VERSION 5.7 ;
  NOWIREEXTENSIONATPIN ON ;
  DIVIDERCHAR "/" ;
  BUSBITCHARS "[]" ;
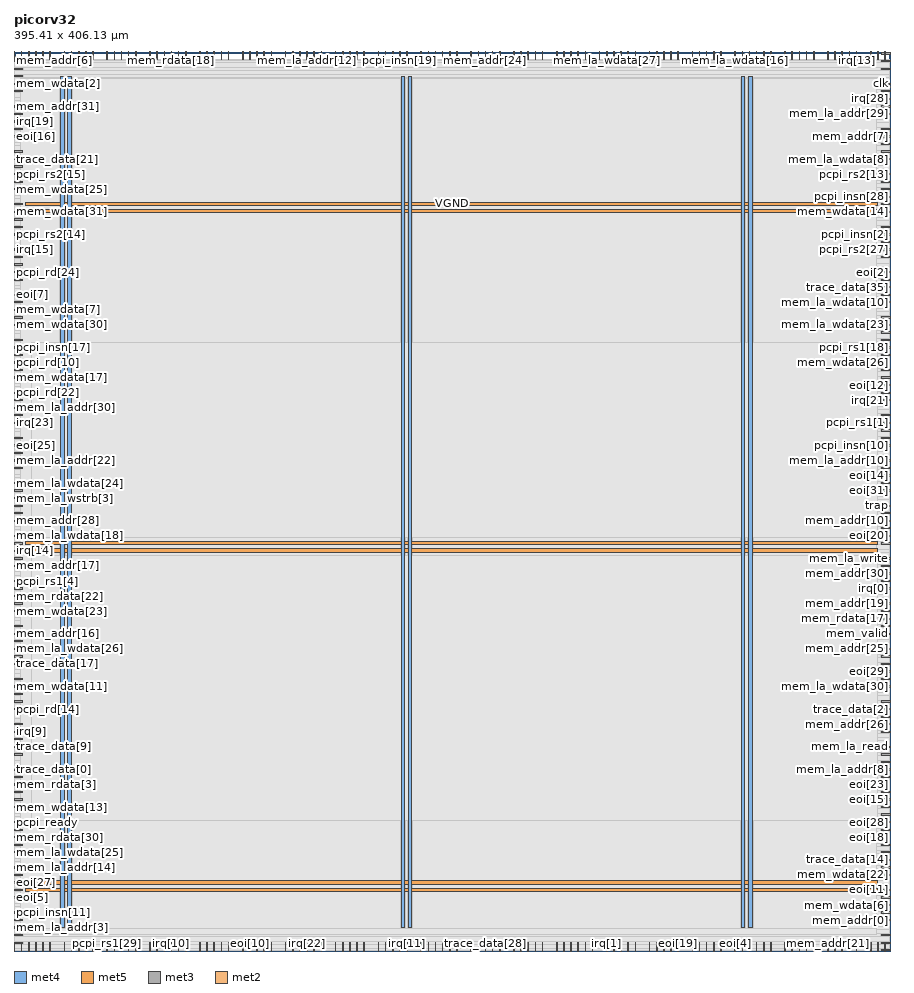
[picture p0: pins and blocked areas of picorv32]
MACRO picorv32
  CLASS BLOCK ;
  FOREIGN picorv32 ;
  ORIGIN 0.000 0.000 ;
  SIZE 395.410 BY 406.130 ;
  PIN VGND
    DIRECTION INOUT ;
    USE GROUND ;
    PORT
      LAYER met4 ;
        RECT 24.340 10.640 25.940 394.640 ;
    END
    PORT
      LAYER met4 ;
        RECT 177.940 10.640 179.540 394.640 ;
    END
    PORT
      LAYER met4 ;
        RECT 331.540 10.640 333.140 394.640 ;
    END
    PORT
      LAYER met5 ;
        RECT 5.280 30.030 389.860 31.630 ;
    END
    PORT
      LAYER met5 ;
        RECT 5.280 183.210 389.860 184.810 ;
    END
    PORT
      LAYER met5 ;
        RECT 5.280 336.390 389.860 337.990 ;
    END
  END VGND
  PIN VPWR
    DIRECTION INOUT ;
    USE POWER ;
    PORT
      LAYER met4 ;
        RECT 21.040 10.640 22.640 394.640 ;
    END
    PORT
      LAYER met4 ;
        RECT 174.640 10.640 176.240 394.640 ;
    END
    PORT
      LAYER met4 ;
        RECT 328.240 10.640 329.840 394.640 ;
    END
    PORT
      LAYER met5 ;
        RECT 5.280 26.730 389.860 28.330 ;
    END
    PORT
      LAYER met5 ;
        RECT 5.280 179.910 389.860 181.510 ;
    END
    PORT
      LAYER met5 ;
        RECT 5.280 333.090 389.860 334.690 ;
    END
  END VPWR
  PIN clk
    DIRECTION INPUT ;
    USE SIGNAL ;
    ANTENNAGATEAREA 1.286700 ;
    ANTENNADIFFAREA 0.434700 ;
    PORT
      LAYER met3 ;
        RECT 391.410 391.040 395.410 391.640 ;
    END
  END clk
  PIN eoi[0]
    DIRECTION OUTPUT TRISTATE ;
    USE SIGNAL ;
    PORT
      LAYER met3 ;
        RECT 0.000 394.440 4.000 395.040 ;
    END
  END eoi[0]
  PIN eoi[10]
    DIRECTION OUTPUT TRISTATE ;
    USE SIGNAL ;
    PORT
      LAYER met2 ;
        RECT 106.350 0.000 106.630 4.000 ;
    END
  END eoi[10]
  PIN eoi[11]
    DIRECTION OUTPUT TRISTATE ;
    USE SIGNAL ;
    PORT
      LAYER met3 ;
        RECT 391.410 27.240 395.410 27.840 ;
    END
  END eoi[11]
  PIN eoi[12]
    DIRECTION OUTPUT TRISTATE ;
    USE SIGNAL ;
    PORT
      LAYER met3 ;
        RECT 391.410 255.040 395.410 255.640 ;
    END
  END eoi[12]
  PIN eoi[13]
    DIRECTION OUTPUT TRISTATE ;
    USE SIGNAL ;
    PORT
      LAYER met2 ;
        RECT 338.190 402.130 338.470 406.130 ;
    END
  END eoi[13]
  PIN eoi[14]
    DIRECTION OUTPUT TRISTATE ;
    USE SIGNAL ;
    PORT
      LAYER met3 ;
        RECT 391.410 214.240 395.410 214.840 ;
    END
  END eoi[14]
  PIN eoi[15]
    DIRECTION OUTPUT TRISTATE ;
    USE SIGNAL ;
    PORT
      LAYER met3 ;
        RECT 391.410 68.040 395.410 68.640 ;
    END
  END eoi[15]
  PIN eoi[16]
    DIRECTION OUTPUT TRISTATE ;
    USE SIGNAL ;
    PORT
      LAYER met3 ;
        RECT 0.000 367.240 4.000 367.840 ;
    END
  END eoi[16]
  PIN eoi[17]
    DIRECTION OUTPUT TRISTATE ;
    USE SIGNAL ;
    PORT
      LAYER met3 ;
        RECT 0.000 326.440 4.000 327.040 ;
    END
  END eoi[17]
  PIN eoi[18]
    DIRECTION OUTPUT TRISTATE ;
    USE SIGNAL ;
    PORT
      LAYER met3 ;
        RECT 391.410 54.440 395.410 55.040 ;
    END
  END eoi[18]
  PIN eoi[19]
    DIRECTION OUTPUT TRISTATE ;
    USE SIGNAL ;
    PORT
      LAYER met2 ;
        RECT 299.550 0.000 299.830 4.000 ;
    END
  END eoi[19]
  PIN eoi[1]
    DIRECTION OUTPUT TRISTATE ;
    USE SIGNAL ;
    PORT
      LAYER met3 ;
        RECT 0.000 17.040 4.000 17.640 ;
    END
  END eoi[1]
  PIN eoi[20]
    DIRECTION OUTPUT TRISTATE ;
    USE SIGNAL ;
    PORT
      LAYER met3 ;
        RECT 391.410 187.040 395.410 187.640 ;
    END
  END eoi[20]
  PIN eoi[21]
    DIRECTION OUTPUT TRISTATE ;
    USE SIGNAL ;
    PORT
      LAYER met3 ;
        RECT 391.410 0.040 395.410 0.640 ;
    END
  END eoi[21]
  PIN eoi[22]
    DIRECTION OUTPUT TRISTATE ;
    USE SIGNAL ;
    PORT
      LAYER met3 ;
        RECT 0.000 370.640 4.000 371.240 ;
    END
  END eoi[22]
  PIN eoi[23]
    DIRECTION OUTPUT TRISTATE ;
    USE SIGNAL ;
    PORT
      LAYER met3 ;
        RECT 391.410 78.240 395.410 78.840 ;
    END
  END eoi[23]
  PIN eoi[24]
    DIRECTION OUTPUT TRISTATE ;
    USE SIGNAL ;
    PORT
      LAYER met2 ;
        RECT 45.170 0.000 45.450 4.000 ;
    END
  END eoi[24]
  PIN eoi[25]
    DIRECTION OUTPUT TRISTATE ;
    USE SIGNAL ;
    PORT
      LAYER met3 ;
        RECT 0.000 227.840 4.000 228.440 ;
    END
  END eoi[25]
  PIN eoi[26]
    DIRECTION OUTPUT TRISTATE ;
    USE SIGNAL ;
    PORT
      LAYER met2 ;
        RECT 164.310 402.130 164.590 406.130 ;
    END
  END eoi[26]
  PIN eoi[27]
    DIRECTION OUTPUT TRISTATE ;
    USE SIGNAL ;
    PORT
      LAYER met3 ;
        RECT 0.000 30.640 4.000 31.240 ;
    END
  END eoi[27]
  PIN eoi[28]
    DIRECTION OUTPUT TRISTATE ;
    USE SIGNAL ;
    PORT
      LAYER met3 ;
        RECT 391.410 57.840 395.410 58.440 ;
    END
  END eoi[28]
  PIN eoi[29]
    DIRECTION OUTPUT TRISTATE ;
    USE SIGNAL ;
    PORT
      LAYER met3 ;
        RECT 391.410 125.840 395.410 126.440 ;
    END
  END eoi[29]
  PIN eoi[2]
    DIRECTION OUTPUT TRISTATE ;
    USE SIGNAL ;
    PORT
      LAYER met3 ;
        RECT 391.410 306.040 395.410 306.640 ;
    END
  END eoi[2]
  PIN eoi[30]
    DIRECTION OUTPUT TRISTATE ;
    USE SIGNAL ;
    PORT
      LAYER met2 ;
        RECT 328.530 0.000 328.810 4.000 ;
    END
  END eoi[30]
  PIN eoi[31]
    DIRECTION OUTPUT TRISTATE ;
    USE SIGNAL ;
    PORT
      LAYER met3 ;
        RECT 391.410 210.840 395.410 211.440 ;
    END
  END eoi[31]
  PIN eoi[3]
    DIRECTION OUTPUT TRISTATE ;
    USE SIGNAL ;
    PORT
      LAYER met2 ;
        RECT 116.010 402.130 116.290 406.130 ;
    END
  END eoi[3]
  PIN eoi[4]
    DIRECTION OUTPUT TRISTATE ;
    USE SIGNAL ;
    PORT
      LAYER met2 ;
        RECT 325.310 0.000 325.590 4.000 ;
    END
  END eoi[4]
  PIN eoi[5]
    DIRECTION OUTPUT TRISTATE ;
    USE SIGNAL ;
    PORT
      LAYER met3 ;
        RECT 0.000 27.240 4.000 27.840 ;
    END
  END eoi[5]
  PIN eoi[6]
    DIRECTION OUTPUT TRISTATE ;
    USE SIGNAL ;
    PORT
      LAYER met2 ;
        RECT 312.430 0.000 312.710 4.000 ;
    END
  END eoi[6]
  PIN eoi[7]
    DIRECTION OUTPUT TRISTATE ;
    USE SIGNAL ;
    PORT
      LAYER met3 ;
        RECT 0.000 292.440 4.000 293.040 ;
    END
  END eoi[7]
  PIN eoi[8]
    DIRECTION OUTPUT TRISTATE ;
    USE SIGNAL ;
    PORT
      LAYER met2 ;
        RECT 289.890 402.130 290.170 406.130 ;
    END
  END eoi[8]
  PIN eoi[9]
    DIRECTION OUTPUT TRISTATE ;
    USE SIGNAL ;
    PORT
      LAYER met2 ;
        RECT 215.830 402.130 216.110 406.130 ;
    END
  END eoi[9]
  PIN irq[0]
    DIRECTION INPUT ;
    USE SIGNAL ;
    PORT
      LAYER met3 ;
        RECT 391.410 163.240 395.410 163.840 ;
    END
  END irq[0]
  PIN irq[10]
    DIRECTION INPUT ;
    USE SIGNAL ;
    PORT
      LAYER met2 ;
        RECT 70.930 0.000 71.210 4.000 ;
    END
  END irq[10]
  PIN irq[11]
    DIRECTION INPUT ;
    USE SIGNAL ;
    PORT
      LAYER met2 ;
        RECT 177.190 0.000 177.470 4.000 ;
    END
  END irq[11]
  PIN irq[12]
    DIRECTION INPUT ;
    USE SIGNAL ;
    PORT
      LAYER met2 ;
        RECT 238.370 402.130 238.650 406.130 ;
    END
  END irq[12]
  PIN irq[13]
    DIRECTION INPUT ;
    USE SIGNAL ;
    PORT
      LAYER met2 ;
        RECT 380.050 402.130 380.330 406.130 ;
    END
  END irq[13]
  PIN irq[14]
    DIRECTION INPUT ;
    USE SIGNAL ;
    PORT
      LAYER met3 ;
        RECT 0.000 180.240 4.000 180.840 ;
    END
  END irq[14]
  PIN irq[15]
    DIRECTION INPUT ;
    USE SIGNAL ;
    PORT
      LAYER met3 ;
        RECT 0.000 316.240 4.000 316.840 ;
    END
  END irq[15]
  PIN irq[16]
    DIRECTION INPUT ;
    USE SIGNAL ;
    PORT
      LAYER met2 ;
        RECT 392.930 402.130 393.210 406.130 ;
    END
  END irq[16]
  PIN irq[17]
    DIRECTION INPUT ;
    USE SIGNAL ;
    PORT
      LAYER met2 ;
        RECT 219.050 402.130 219.330 406.130 ;
    END
  END irq[17]
  PIN irq[18]
    DIRECTION INPUT ;
    USE SIGNAL ;
    PORT
      LAYER met2 ;
        RECT 296.330 402.130 296.610 406.130 ;
    END
  END irq[18]
  PIN irq[19]
    DIRECTION INPUT ;
    USE SIGNAL ;
    PORT
      LAYER met3 ;
        RECT 0.000 374.040 4.000 374.640 ;
    END
  END irq[19]
  PIN irq[1]
    DIRECTION INPUT ;
    USE SIGNAL ;
    PORT
      LAYER met2 ;
        RECT 267.350 0.000 267.630 4.000 ;
    END
  END irq[1]
  PIN irq[20]
    DIRECTION INPUT ;
    USE SIGNAL ;
    PORT
      LAYER met3 ;
        RECT 0.000 401.240 4.000 401.840 ;
    END
  END irq[20]
  PIN irq[21]
    DIRECTION INPUT ;
    USE SIGNAL ;
    PORT
      LAYER met3 ;
        RECT 391.410 248.240 395.410 248.840 ;
    END
  END irq[21]
  PIN irq[22]
    DIRECTION INPUT ;
    USE SIGNAL ;
    PORT
      LAYER met2 ;
        RECT 132.110 0.000 132.390 4.000 ;
    END
  END irq[22]
  PIN irq[23]
    DIRECTION INPUT ;
    USE SIGNAL ;
    PORT
      LAYER met3 ;
        RECT 0.000 238.040 4.000 238.640 ;
    END
  END irq[23]
  PIN irq[24]
    DIRECTION INPUT ;
    USE SIGNAL ;
    PORT
      LAYER met3 ;
        RECT 391.410 404.640 395.410 405.240 ;
    END
  END irq[24]
  PIN irq[25]
    DIRECTION INPUT ;
    USE SIGNAL ;
    PORT
      LAYER met2 ;
        RECT 93.470 402.130 93.750 406.130 ;
    END
  END irq[25]
  PIN irq[26]
    DIRECTION INPUT ;
    USE SIGNAL ;
    PORT
      LAYER met2 ;
        RECT 164.310 0.000 164.590 4.000 ;
    END
  END irq[26]
  PIN irq[27]
    DIRECTION INPUT ;
    USE SIGNAL ;
    PORT
      LAYER met2 ;
        RECT 196.510 402.130 196.790 406.130 ;
    END
  END irq[27]
  PIN irq[28]
    DIRECTION INPUT ;
    USE SIGNAL ;
    PORT
      LAYER met3 ;
        RECT 391.410 384.240 395.410 384.840 ;
    END
  END irq[28]
  PIN irq[29]
    DIRECTION INPUT ;
    USE SIGNAL ;
    PORT
      LAYER met3 ;
        RECT 391.410 47.640 395.410 48.240 ;
    END
  END irq[29]
  PIN irq[2]
    DIRECTION INPUT ;
    USE SIGNAL ;
    PORT
      LAYER met3 ;
        RECT 0.000 122.440 4.000 123.040 ;
    END
  END irq[2]
  PIN irq[30]
    DIRECTION INPUT ;
    USE SIGNAL ;
    PORT
      LAYER met2 ;
        RECT 228.710 0.000 228.990 4.000 ;
    END
  END irq[30]
  PIN irq[31]
    DIRECTION INPUT ;
    USE SIGNAL ;
    PORT
      LAYER met2 ;
        RECT 90.250 402.130 90.530 406.130 ;
    END
  END irq[31]
  PIN irq[3]
    DIRECTION INPUT ;
    USE SIGNAL ;
    PORT
      LAYER met2 ;
        RECT 35.510 0.000 35.790 4.000 ;
    END
  END irq[3]
  PIN irq[4]
    DIRECTION INPUT ;
    USE SIGNAL ;
    PORT
      LAYER met2 ;
        RECT 74.150 402.130 74.430 406.130 ;
    END
  END irq[4]
  PIN irq[5]
    DIRECTION INPUT ;
    USE SIGNAL ;
    PORT
      LAYER met3 ;
        RECT 391.410 360.440 395.410 361.040 ;
    END
  END irq[5]
  PIN irq[6]
    DIRECTION INPUT ;
    USE SIGNAL ;
    PORT
      LAYER met3 ;
        RECT 0.000 88.440 4.000 89.040 ;
    END
  END irq[6]
  PIN irq[7]
    DIRECTION INPUT ;
    USE SIGNAL ;
    PORT
      LAYER met2 ;
        RECT 6.530 402.130 6.810 406.130 ;
    END
  END irq[7]
  PIN irq[8]
    DIRECTION INPUT ;
    USE SIGNAL ;
    PORT
      LAYER met2 ;
        RECT 277.010 0.000 277.290 4.000 ;
    END
  END irq[8]
  PIN irq[9]
    DIRECTION INPUT ;
    USE SIGNAL ;
    PORT
      LAYER met3 ;
        RECT 0.000 98.640 4.000 99.240 ;
    END
  END irq[9]
  PIN mem_addr[0]
    DIRECTION OUTPUT TRISTATE ;
    USE SIGNAL ;
    PORT
      LAYER met3 ;
        RECT 391.410 13.640 395.410 14.240 ;
    END
  END mem_addr[0]
  PIN mem_addr[10]
    DIRECTION OUTPUT TRISTATE ;
    USE SIGNAL ;
    ANTENNADIFFAREA 0.795200 ;
    PORT
      LAYER met3 ;
        RECT 391.410 193.840 395.410 194.440 ;
    END
  END mem_addr[10]
  PIN mem_addr[11]
    DIRECTION OUTPUT TRISTATE ;
    USE SIGNAL ;
    ANTENNADIFFAREA 0.795200 ;
    PORT
      LAYER met3 ;
        RECT 391.410 346.840 395.410 347.440 ;
    END
  END mem_addr[11]
  PIN mem_addr[12]
    DIRECTION OUTPUT TRISTATE ;
    USE SIGNAL ;
    ANTENNADIFFAREA 0.795200 ;
    PORT
      LAYER met3 ;
        RECT 391.410 44.240 395.410 44.840 ;
    END
  END mem_addr[12]
  PIN mem_addr[13]
    DIRECTION OUTPUT TRISTATE ;
    USE SIGNAL ;
    ANTENNADIFFAREA 0.795200 ;
    PORT
      LAYER met2 ;
        RECT 228.710 402.130 228.990 406.130 ;
    END
  END mem_addr[13]
  PIN mem_addr[14]
    DIRECTION OUTPUT TRISTATE ;
    USE SIGNAL ;
    ANTENNADIFFAREA 0.795200 ;
    PORT
      LAYER met2 ;
        RECT 328.530 402.130 328.810 406.130 ;
    END
  END mem_addr[14]
  PIN mem_addr[15]
    DIRECTION OUTPUT TRISTATE ;
    USE SIGNAL ;
    ANTENNADIFFAREA 0.795200 ;
    PORT
      LAYER met2 ;
        RECT 231.930 0.000 232.210 4.000 ;
    END
  END mem_addr[15]
  PIN mem_addr[16]
    DIRECTION OUTPUT TRISTATE ;
    USE SIGNAL ;
    ANTENNADIFFAREA 0.795200 ;
    PORT
      LAYER met3 ;
        RECT 0.000 142.840 4.000 143.440 ;
    END
  END mem_addr[16]
  PIN mem_addr[17]
    DIRECTION OUTPUT TRISTATE ;
    USE SIGNAL ;
    ANTENNADIFFAREA 0.795200 ;
    PORT
      LAYER met3 ;
        RECT 0.000 173.440 4.000 174.040 ;
    END
  END mem_addr[17]
  PIN mem_addr[18]
    DIRECTION OUTPUT TRISTATE ;
    USE SIGNAL ;
    ANTENNADIFFAREA 0.795200 ;
    PORT
      LAYER met2 ;
        RECT 61.270 402.130 61.550 406.130 ;
    END
  END mem_addr[18]
  PIN mem_addr[19]
    DIRECTION OUTPUT TRISTATE ;
    USE SIGNAL ;
    ANTENNADIFFAREA 0.795200 ;
    PORT
      LAYER met3 ;
        RECT 391.410 156.440 395.410 157.040 ;
    END
  END mem_addr[19]
  PIN mem_addr[1]
    DIRECTION OUTPUT TRISTATE ;
    USE SIGNAL ;
    PORT
      LAYER met2 ;
        RECT 90.250 0.000 90.530 4.000 ;
    END
  END mem_addr[1]
  PIN mem_addr[20]
    DIRECTION OUTPUT TRISTATE ;
    USE SIGNAL ;
    ANTENNADIFFAREA 0.795200 ;
    PORT
      LAYER met3 ;
        RECT 0.000 6.840 4.000 7.440 ;
    END
  END mem_addr[20]
  PIN mem_addr[21]
    DIRECTION OUTPUT TRISTATE ;
    USE SIGNAL ;
    ANTENNADIFFAREA 0.795200 ;
    PORT
      LAYER met2 ;
        RECT 367.170 0.000 367.450 4.000 ;
    END
  END mem_addr[21]
  PIN mem_addr[22]
    DIRECTION OUTPUT TRISTATE ;
    USE SIGNAL ;
    ANTENNADIFFAREA 0.795200 ;
    PORT
      LAYER met2 ;
        RECT 238.370 0.000 238.650 4.000 ;
    END
  END mem_addr[22]
  PIN mem_addr[23]
    DIRECTION OUTPUT TRISTATE ;
    USE SIGNAL ;
    ANTENNADIFFAREA 0.795200 ;
    PORT
      LAYER met2 ;
        RECT 360.730 0.000 361.010 4.000 ;
    END
  END mem_addr[23]
  PIN mem_addr[24]
    DIRECTION OUTPUT TRISTATE ;
    USE SIGNAL ;
    ANTENNADIFFAREA 0.795200 ;
    PORT
      LAYER met2 ;
        RECT 212.610 402.130 212.890 406.130 ;
    END
  END mem_addr[24]
  PIN mem_addr[25]
    DIRECTION OUTPUT TRISTATE ;
    USE SIGNAL ;
    ANTENNADIFFAREA 0.795200 ;
    PORT
      LAYER met3 ;
        RECT 391.410 136.040 395.410 136.640 ;
    END
  END mem_addr[25]
  PIN mem_addr[26]
    DIRECTION OUTPUT TRISTATE ;
    USE SIGNAL ;
    ANTENNADIFFAREA 0.795200 ;
    PORT
      LAYER met3 ;
        RECT 391.410 102.040 395.410 102.640 ;
    END
  END mem_addr[26]
  PIN mem_addr[27]
    DIRECTION OUTPUT TRISTATE ;
    USE SIGNAL ;
    ANTENNADIFFAREA 0.795200 ;
    PORT
      LAYER met3 ;
        RECT 0.000 275.440 4.000 276.040 ;
    END
  END mem_addr[27]
  PIN mem_addr[28]
    DIRECTION OUTPUT TRISTATE ;
    USE SIGNAL ;
    ANTENNADIFFAREA 0.795200 ;
    PORT
      LAYER met3 ;
        RECT 0.000 193.840 4.000 194.440 ;
    END
  END mem_addr[28]
  PIN mem_addr[29]
    DIRECTION OUTPUT TRISTATE ;
    USE SIGNAL ;
    ANTENNADIFFAREA 0.795200 ;
    PORT
      LAYER met2 ;
        RECT 96.690 402.130 96.970 406.130 ;
    END
  END mem_addr[29]
  PIN mem_addr[2]
    DIRECTION OUTPUT TRISTATE ;
    USE SIGNAL ;
    ANTENNADIFFAREA 0.795200 ;
    PORT
      LAYER met2 ;
        RECT 154.650 0.000 154.930 4.000 ;
    END
  END mem_addr[2]
  PIN mem_addr[30]
    DIRECTION OUTPUT TRISTATE ;
    USE SIGNAL ;
    ANTENNADIFFAREA 0.795200 ;
    PORT
      LAYER met3 ;
        RECT 391.410 170.040 395.410 170.640 ;
    END
  END mem_addr[30]
  PIN mem_addr[31]
    DIRECTION OUTPUT TRISTATE ;
    USE SIGNAL ;
    ANTENNADIFFAREA 0.795200 ;
    PORT
      LAYER met3 ;
        RECT 0.000 377.440 4.000 378.040 ;
    END
  END mem_addr[31]
  PIN mem_addr[3]
    DIRECTION OUTPUT TRISTATE ;
    USE SIGNAL ;
    ANTENNADIFFAREA 0.795200 ;
    PORT
      LAYER met2 ;
        RECT 251.250 0.000 251.530 4.000 ;
    END
  END mem_addr[3]
  PIN mem_addr[4]
    DIRECTION OUTPUT TRISTATE ;
    USE SIGNAL ;
    ANTENNADIFFAREA 0.795200 ;
    PORT
      LAYER met3 ;
        RECT 0.000 285.640 4.000 286.240 ;
    END
  END mem_addr[4]
  PIN mem_addr[5]
    DIRECTION OUTPUT TRISTATE ;
    USE SIGNAL ;
    ANTENNADIFFAREA 0.795200 ;
    PORT
      LAYER met2 ;
        RECT 231.930 402.130 232.210 406.130 ;
    END
  END mem_addr[5]
  PIN mem_addr[6]
    DIRECTION OUTPUT TRISTATE ;
    USE SIGNAL ;
    ANTENNADIFFAREA 0.795200 ;
    PORT
      LAYER met2 ;
        RECT 16.190 402.130 16.470 406.130 ;
    END
  END mem_addr[6]
  PIN mem_addr[7]
    DIRECTION OUTPUT TRISTATE ;
    USE SIGNAL ;
    ANTENNADIFFAREA 0.445500 ;
    PORT
      LAYER met3 ;
        RECT 391.410 367.240 395.410 367.840 ;
    END
  END mem_addr[7]
  PIN mem_addr[8]
    DIRECTION OUTPUT TRISTATE ;
    USE SIGNAL ;
    ANTENNADIFFAREA 0.795200 ;
    PORT
      LAYER met2 ;
        RECT 25.850 0.000 26.130 4.000 ;
    END
  END mem_addr[8]
  PIN mem_addr[9]
    DIRECTION OUTPUT TRISTATE ;
    USE SIGNAL ;
    ANTENNADIFFAREA 0.795200 ;
    PORT
      LAYER met3 ;
        RECT 0.000 387.640 4.000 388.240 ;
    END
  END mem_addr[9]
  PIN mem_instr
    DIRECTION OUTPUT TRISTATE ;
    USE SIGNAL ;
    ANTENNADIFFAREA 0.795200 ;
    PORT
      LAYER met3 ;
        RECT 0.000 360.440 4.000 361.040 ;
    END
  END mem_instr
  PIN mem_la_addr[0]
    DIRECTION OUTPUT TRISTATE ;
    USE SIGNAL ;
    PORT
      LAYER met3 ;
        RECT 0.000 78.240 4.000 78.840 ;
    END
  END mem_la_addr[0]
  PIN mem_la_addr[10]
    DIRECTION OUTPUT TRISTATE ;
    USE SIGNAL ;
    ANTENNADIFFAREA 0.445500 ;
    PORT
      LAYER met3 ;
        RECT 391.410 221.040 395.410 221.640 ;
    END
  END mem_la_addr[10]
  PIN mem_la_addr[11]
    DIRECTION OUTPUT TRISTATE ;
    USE SIGNAL ;
    ANTENNADIFFAREA 0.795200 ;
    PORT
      LAYER met2 ;
        RECT 0.090 402.130 0.370 406.130 ;
    END
  END mem_la_addr[11]
  PIN mem_la_addr[12]
    DIRECTION OUTPUT TRISTATE ;
    USE SIGNAL ;
    ANTENNADIFFAREA 0.795200 ;
    PORT
      LAYER met2 ;
        RECT 132.110 402.130 132.390 406.130 ;
    END
  END mem_la_addr[12]
  PIN mem_la_addr[13]
    DIRECTION OUTPUT TRISTATE ;
    USE SIGNAL ;
    ANTENNADIFFAREA 0.795200 ;
    PORT
      LAYER met2 ;
        RECT 190.070 0.000 190.350 4.000 ;
    END
  END mem_la_addr[13]
  PIN mem_la_addr[14]
    DIRECTION OUTPUT TRISTATE ;
    USE SIGNAL ;
    ANTENNADIFFAREA 0.795200 ;
    PORT
      LAYER met3 ;
        RECT 0.000 37.440 4.000 38.040 ;
    END
  END mem_la_addr[14]
  PIN mem_la_addr[15]
    DIRECTION OUTPUT TRISTATE ;
    USE SIGNAL ;
    ANTENNADIFFAREA 0.795200 ;
    PORT
      LAYER met2 ;
        RECT 251.250 402.130 251.530 406.130 ;
    END
  END mem_la_addr[15]
  PIN mem_la_addr[16]
    DIRECTION OUTPUT TRISTATE ;
    USE SIGNAL ;
    ANTENNADIFFAREA 0.445500 ;
    PORT
      LAYER met3 ;
        RECT 391.410 278.840 395.410 279.440 ;
    END
  END mem_la_addr[16]
  PIN mem_la_addr[17]
    DIRECTION OUTPUT TRISTATE ;
    USE SIGNAL ;
    ANTENNADIFFAREA 0.795200 ;
    PORT
      LAYER met2 ;
        RECT 3.310 402.130 3.590 406.130 ;
    END
  END mem_la_addr[17]
  PIN mem_la_addr[18]
    DIRECTION OUTPUT TRISTATE ;
    USE SIGNAL ;
    ANTENNADIFFAREA 0.795200 ;
    PORT
      LAYER met2 ;
        RECT 257.690 0.000 257.970 4.000 ;
    END
  END mem_la_addr[18]
  PIN mem_la_addr[19]
    DIRECTION OUTPUT TRISTATE ;
    USE SIGNAL ;
    ANTENNADIFFAREA 0.795200 ;
    PORT
      LAYER met2 ;
        RECT 376.830 0.000 377.110 4.000 ;
    END
  END mem_la_addr[19]
  PIN mem_la_addr[1]
    DIRECTION OUTPUT TRISTATE ;
    USE SIGNAL ;
    PORT
      LAYER met3 ;
        RECT 391.410 71.440 395.410 72.040 ;
    END
  END mem_la_addr[1]
  PIN mem_la_addr[20]
    DIRECTION OUTPUT TRISTATE ;
    USE SIGNAL ;
    ANTENNADIFFAREA 0.795200 ;
    PORT
      LAYER met2 ;
        RECT 9.750 402.130 10.030 406.130 ;
    END
  END mem_la_addr[20]
  PIN mem_la_addr[21]
    DIRECTION OUTPUT TRISTATE ;
    USE SIGNAL ;
    ANTENNADIFFAREA 0.795200 ;
    PORT
      LAYER met2 ;
        RECT 170.750 402.130 171.030 406.130 ;
    END
  END mem_la_addr[21]
  PIN mem_la_addr[22]
    DIRECTION OUTPUT TRISTATE ;
    USE SIGNAL ;
    ANTENNADIFFAREA 0.795200 ;
    PORT
      LAYER met3 ;
        RECT 0.000 224.440 4.000 225.040 ;
    END
  END mem_la_addr[22]
  PIN mem_la_addr[23]
    DIRECTION OUTPUT TRISTATE ;
    USE SIGNAL ;
    ANTENNADIFFAREA 0.795200 ;
    PORT
      LAYER met2 ;
        RECT 77.370 402.130 77.650 406.130 ;
    END
  END mem_la_addr[23]
  PIN mem_la_addr[24]
    DIRECTION OUTPUT TRISTATE ;
    USE SIGNAL ;
    ANTENNADIFFAREA 0.795200 ;
    PORT
      LAYER met2 ;
        RECT 51.610 402.130 51.890 406.130 ;
    END
  END mem_la_addr[24]
  PIN mem_la_addr[25]
    DIRECTION OUTPUT TRISTATE ;
    USE SIGNAL ;
    ANTENNADIFFAREA 0.795200 ;
    PORT
      LAYER met3 ;
        RECT 391.410 343.440 395.410 344.040 ;
    END
  END mem_la_addr[25]
  PIN mem_la_addr[26]
    DIRECTION OUTPUT TRISTATE ;
    USE SIGNAL ;
    ANTENNADIFFAREA 0.795200 ;
    PORT
      LAYER met2 ;
        RECT 48.390 402.130 48.670 406.130 ;
    END
  END mem_la_addr[26]
  PIN mem_la_addr[27]
    DIRECTION OUTPUT TRISTATE ;
    USE SIGNAL ;
    ANTENNADIFFAREA 0.795200 ;
    PORT
      LAYER met3 ;
        RECT 391.410 88.440 395.410 89.040 ;
    END
  END mem_la_addr[27]
  PIN mem_la_addr[28]
    DIRECTION OUTPUT TRISTATE ;
    USE SIGNAL ;
    ANTENNADIFFAREA 0.795200 ;
    PORT
      LAYER met2 ;
        RECT 22.630 402.130 22.910 406.130 ;
    END
  END mem_la_addr[28]
  PIN mem_la_addr[29]
    DIRECTION OUTPUT TRISTATE ;
    USE SIGNAL ;
    ANTENNADIFFAREA 0.795200 ;
    PORT
      LAYER met3 ;
        RECT 391.410 377.440 395.410 378.040 ;
    END
  END mem_la_addr[29]
  PIN mem_la_addr[2]
    DIRECTION OUTPUT TRISTATE ;
    USE SIGNAL ;
    ANTENNADIFFAREA 0.795200 ;
    PORT
      LAYER met3 ;
        RECT 391.410 149.640 395.410 150.240 ;
    END
  END mem_la_addr[2]
  PIN mem_la_addr[30]
    DIRECTION OUTPUT TRISTATE ;
    USE SIGNAL ;
    ANTENNADIFFAREA 0.795200 ;
    PORT
      LAYER met3 ;
        RECT 0.000 241.440 4.000 242.040 ;
    END
  END mem_la_addr[30]
  PIN mem_la_addr[31]
    DIRECTION OUTPUT TRISTATE ;
    USE SIGNAL ;
    ANTENNADIFFAREA 0.795200 ;
    PORT
      LAYER met2 ;
        RECT 138.550 0.000 138.830 4.000 ;
    END
  END mem_la_addr[31]
  PIN mem_la_addr[3]
    DIRECTION OUTPUT TRISTATE ;
    USE SIGNAL ;
    ANTENNADIFFAREA 0.795200 ;
    PORT
      LAYER met3 ;
        RECT 0.000 10.240 4.000 10.840 ;
    END
  END mem_la_addr[3]
  PIN mem_la_addr[4]
    DIRECTION OUTPUT TRISTATE ;
    USE SIGNAL ;
    ANTENNADIFFAREA 0.795200 ;
    PORT
      LAYER met3 ;
        RECT 391.410 326.440 395.410 327.040 ;
    END
  END mem_la_addr[4]
  PIN mem_la_addr[5]
    DIRECTION OUTPUT TRISTATE ;
    USE SIGNAL ;
    ANTENNADIFFAREA 0.795200 ;
    PORT
      LAYER met2 ;
        RECT 331.750 0.000 332.030 4.000 ;
    END
  END mem_la_addr[5]
  PIN mem_la_addr[6]
    DIRECTION OUTPUT TRISTATE ;
    USE SIGNAL ;
    ANTENNADIFFAREA 0.795200 ;
    PORT
      LAYER met3 ;
        RECT 391.410 336.640 395.410 337.240 ;
    END
  END mem_la_addr[6]
  PIN mem_la_addr[7]
    DIRECTION OUTPUT TRISTATE ;
    USE SIGNAL ;
    ANTENNADIFFAREA 0.795200 ;
    PORT
      LAYER met2 ;
        RECT 116.010 0.000 116.290 4.000 ;
    END
  END mem_la_addr[7]
  PIN mem_la_addr[8]
    DIRECTION OUTPUT TRISTATE ;
    USE SIGNAL ;
    ANTENNADIFFAREA 0.795200 ;
    PORT
      LAYER met3 ;
        RECT 391.410 81.640 395.410 82.240 ;
    END
  END mem_la_addr[8]
  PIN mem_la_addr[9]
    DIRECTION OUTPUT TRISTATE ;
    USE SIGNAL ;
    ANTENNADIFFAREA 0.795200 ;
    PORT
      LAYER met2 ;
        RECT 125.670 0.000 125.950 4.000 ;
    END
  END mem_la_addr[9]
  PIN mem_la_read
    DIRECTION OUTPUT TRISTATE ;
    USE SIGNAL ;
    ANTENNADIFFAREA 0.795200 ;
    PORT
      LAYER met3 ;
        RECT 391.410 91.840 395.410 92.440 ;
    END
  END mem_la_read
  PIN mem_la_wdata[0]
    DIRECTION OUTPUT TRISTATE ;
    USE SIGNAL ;
    ANTENNADIFFAREA 0.795200 ;
    PORT
      LAYER met2 ;
        RECT 347.850 402.130 348.130 406.130 ;
    END
  END mem_la_wdata[0]
  PIN mem_la_wdata[10]
    DIRECTION OUTPUT TRISTATE ;
    USE SIGNAL ;
    ANTENNADIFFAREA 0.795200 ;
    PORT
      LAYER met3 ;
        RECT 391.410 292.440 395.410 293.040 ;
    END
  END mem_la_wdata[10]
  PIN mem_la_wdata[11]
    DIRECTION OUTPUT TRISTATE ;
    USE SIGNAL ;
    ANTENNADIFFAREA 0.795200 ;
    PORT
      LAYER met2 ;
        RECT 190.070 402.130 190.350 406.130 ;
    END
  END mem_la_wdata[11]
  PIN mem_la_wdata[12]
    DIRECTION OUTPUT TRISTATE ;
    USE SIGNAL ;
    ANTENNADIFFAREA 0.795200 ;
    PORT
      LAYER met2 ;
        RECT 67.710 402.130 67.990 406.130 ;
    END
  END mem_la_wdata[12]
  PIN mem_la_wdata[13]
    DIRECTION OUTPUT TRISTATE ;
    USE SIGNAL ;
    ANTENNADIFFAREA 0.795200 ;
    PORT
      LAYER met2 ;
        RECT 286.670 0.000 286.950 4.000 ;
    END
  END mem_la_wdata[13]
  PIN mem_la_wdata[14]
    DIRECTION OUTPUT TRISTATE ;
    USE SIGNAL ;
    ANTENNADIFFAREA 0.795200 ;
    PORT
      LAYER met3 ;
        RECT 0.000 329.840 4.000 330.440 ;
    END
  END mem_la_wdata[14]
  PIN mem_la_wdata[15]
    DIRECTION OUTPUT TRISTATE ;
    USE SIGNAL ;
    ANTENNADIFFAREA 0.795200 ;
    PORT
      LAYER met2 ;
        RECT 151.430 402.130 151.710 406.130 ;
    END
  END mem_la_wdata[15]
  PIN mem_la_wdata[16]
    DIRECTION OUTPUT TRISTATE ;
    USE SIGNAL ;
    ANTENNADIFFAREA 0.795200 ;
    PORT
      LAYER met2 ;
        RECT 325.310 402.130 325.590 406.130 ;
    END
  END mem_la_wdata[16]
  PIN mem_la_wdata[17]
    DIRECTION OUTPUT TRISTATE ;
    USE SIGNAL ;
    ANTENNADIFFAREA 0.795200 ;
    PORT
      LAYER met2 ;
        RECT 360.730 402.130 361.010 406.130 ;
    END
  END mem_la_wdata[17]
  PIN mem_la_wdata[18]
    DIRECTION OUTPUT TRISTATE ;
    USE SIGNAL ;
    ANTENNADIFFAREA 0.795200 ;
    PORT
      LAYER met3 ;
        RECT 0.000 187.040 4.000 187.640 ;
    END
  END mem_la_wdata[18]
  PIN mem_la_wdata[19]
    DIRECTION OUTPUT TRISTATE ;
    USE SIGNAL ;
    ANTENNADIFFAREA 0.795200 ;
    PORT
      LAYER met2 ;
        RECT 128.890 0.000 129.170 4.000 ;
    END
  END mem_la_wdata[19]
  PIN mem_la_wdata[1]
    DIRECTION OUTPUT TRISTATE ;
    USE SIGNAL ;
    ANTENNADIFFAREA 0.795200 ;
    PORT
      LAYER met2 ;
        RECT 183.630 0.000 183.910 4.000 ;
    END
  END mem_la_wdata[1]
  PIN mem_la_wdata[20]
    DIRECTION OUTPUT TRISTATE ;
    USE SIGNAL ;
    ANTENNADIFFAREA 0.795200 ;
    PORT
      LAYER met3 ;
        RECT 391.410 285.640 395.410 286.240 ;
    END
  END mem_la_wdata[20]
  PIN mem_la_wdata[21]
    DIRECTION OUTPUT TRISTATE ;
    USE SIGNAL ;
    ANTENNADIFFAREA 0.795200 ;
    PORT
      LAYER met3 ;
        RECT 391.410 234.640 395.410 235.240 ;
    END
  END mem_la_wdata[21]
  PIN mem_la_wdata[22]
    DIRECTION OUTPUT TRISTATE ;
    USE SIGNAL ;
    ANTENNADIFFAREA 0.795200 ;
    PORT
      LAYER met2 ;
        RECT 386.490 0.000 386.770 4.000 ;
    END
  END mem_la_wdata[22]
  PIN mem_la_wdata[23]
    DIRECTION OUTPUT TRISTATE ;
    USE SIGNAL ;
    ANTENNADIFFAREA 0.795200 ;
    PORT
      LAYER met3 ;
        RECT 391.410 282.240 395.410 282.840 ;
    END
  END mem_la_wdata[23]
  PIN mem_la_wdata[24]
    DIRECTION OUTPUT TRISTATE ;
    USE SIGNAL ;
    ANTENNADIFFAREA 0.795200 ;
    PORT
      LAYER met3 ;
        RECT 0.000 210.840 4.000 211.440 ;
    END
  END mem_la_wdata[24]
  PIN mem_la_wdata[25]
    DIRECTION OUTPUT TRISTATE ;
    USE SIGNAL ;
    ANTENNADIFFAREA 0.795200 ;
    PORT
      LAYER met3 ;
        RECT 0.000 44.240 4.000 44.840 ;
    END
  END mem_la_wdata[25]
  PIN mem_la_wdata[26]
    DIRECTION OUTPUT TRISTATE ;
    USE SIGNAL ;
    ANTENNADIFFAREA 0.795200 ;
    PORT
      LAYER met3 ;
        RECT 0.000 139.440 4.000 140.040 ;
    END
  END mem_la_wdata[26]
  PIN mem_la_wdata[27]
    DIRECTION OUTPUT TRISTATE ;
    USE SIGNAL ;
    ANTENNADIFFAREA 0.795200 ;
    PORT
      LAYER met2 ;
        RECT 267.350 402.130 267.630 406.130 ;
    END
  END mem_la_wdata[27]
  PIN mem_la_wdata[28]
    DIRECTION OUTPUT TRISTATE ;
    USE SIGNAL ;
    ANTENNADIFFAREA 0.795200 ;
    PORT
      LAYER met2 ;
        RECT 93.470 0.000 93.750 4.000 ;
    END
  END mem_la_wdata[28]
  PIN mem_la_wdata[29]
    DIRECTION OUTPUT TRISTATE ;
    USE SIGNAL ;
    ANTENNADIFFAREA 0.795200 ;
    PORT
      LAYER met2 ;
        RECT 167.530 402.130 167.810 406.130 ;
    END
  END mem_la_wdata[29]
  PIN mem_la_wdata[2]
    DIRECTION OUTPUT TRISTATE ;
    USE SIGNAL ;
    ANTENNADIFFAREA 0.795200 ;
    PORT
      LAYER met2 ;
        RECT 173.970 0.000 174.250 4.000 ;
    END
  END mem_la_wdata[2]
  PIN mem_la_wdata[30]
    DIRECTION OUTPUT TRISTATE ;
    USE SIGNAL ;
    ANTENNADIFFAREA 0.445500 ;
    PORT
      LAYER met3 ;
        RECT 391.410 119.040 395.410 119.640 ;
    END
  END mem_la_wdata[30]
  PIN mem_la_wdata[31]
    DIRECTION OUTPUT TRISTATE ;
    USE SIGNAL ;
    ANTENNADIFFAREA 0.795200 ;
    PORT
      LAYER met2 ;
        RECT 25.850 402.130 26.130 406.130 ;
    END
  END mem_la_wdata[31]
  PIN mem_la_wdata[3]
    DIRECTION OUTPUT TRISTATE ;
    USE SIGNAL ;
    ANTENNADIFFAREA 0.795200 ;
    PORT
      LAYER met3 ;
        RECT 391.410 98.640 395.410 99.240 ;
    END
  END mem_la_wdata[3]
  PIN mem_la_wdata[4]
    DIRECTION OUTPUT TRISTATE ;
    USE SIGNAL ;
    ANTENNADIFFAREA 0.795200 ;
    PORT
      LAYER met3 ;
        RECT 0.000 112.240 4.000 112.840 ;
    END
  END mem_la_wdata[4]
  PIN mem_la_wdata[5]
    DIRECTION OUTPUT TRISTATE ;
    USE SIGNAL ;
    ANTENNADIFFAREA 0.795200 ;
    PORT
      LAYER met2 ;
        RECT 254.470 0.000 254.750 4.000 ;
    END
  END mem_la_wdata[5]
  PIN mem_la_wdata[6]
    DIRECTION OUTPUT TRISTATE ;
    USE SIGNAL ;
    ANTENNADIFFAREA 0.795200 ;
    PORT
      LAYER met3 ;
        RECT 391.410 397.840 395.410 398.440 ;
    END
  END mem_la_wdata[6]
  PIN mem_la_wdata[7]
    DIRECTION OUTPUT TRISTATE ;
    USE SIGNAL ;
    ANTENNADIFFAREA 0.795200 ;
    PORT
      LAYER met2 ;
        RECT 135.330 0.000 135.610 4.000 ;
    END
  END mem_la_wdata[7]
  PIN mem_la_wdata[8]
    DIRECTION OUTPUT TRISTATE ;
    USE SIGNAL ;
    ANTENNADIFFAREA 0.795200 ;
    PORT
      LAYER met3 ;
        RECT 391.410 357.040 395.410 357.640 ;
    END
  END mem_la_wdata[8]
  PIN mem_la_wdata[9]
    DIRECTION OUTPUT TRISTATE ;
    USE SIGNAL ;
    ANTENNADIFFAREA 0.795200 ;
    PORT
      LAYER met3 ;
        RECT 0.000 176.840 4.000 177.440 ;
    END
  END mem_la_wdata[9]
  PIN mem_la_write
    DIRECTION OUTPUT TRISTATE ;
    USE SIGNAL ;
    ANTENNADIFFAREA 0.795200 ;
    PORT
      LAYER met3 ;
        RECT 391.410 176.840 395.410 177.440 ;
    END
  END mem_la_write
  PIN mem_la_wstrb[0]
    DIRECTION OUTPUT TRISTATE ;
    USE SIGNAL ;
    ANTENNADIFFAREA 0.795200 ;
    PORT
      LAYER met3 ;
        RECT 0.000 309.440 4.000 310.040 ;
    END
  END mem_la_wstrb[0]
  PIN mem_la_wstrb[1]
    DIRECTION OUTPUT TRISTATE ;
    USE SIGNAL ;
    ANTENNADIFFAREA 0.795200 ;
    PORT
      LAYER met3 ;
        RECT 0.000 251.640 4.000 252.240 ;
    END
  END mem_la_wstrb[1]
  PIN mem_la_wstrb[2]
    DIRECTION OUTPUT TRISTATE ;
    USE SIGNAL ;
    ANTENNADIFFAREA 0.795200 ;
    PORT
      LAYER met2 ;
        RECT 280.230 402.130 280.510 406.130 ;
    END
  END mem_la_wstrb[2]
  PIN mem_la_wstrb[3]
    DIRECTION OUTPUT TRISTATE ;
    USE SIGNAL ;
    ANTENNADIFFAREA 0.795200 ;
    PORT
      LAYER met3 ;
        RECT 0.000 204.040 4.000 204.640 ;
    END
  END mem_la_wstrb[3]
  PIN mem_rdata[0]
    DIRECTION INPUT ;
    USE SIGNAL ;
    ANTENNAGATEAREA 0.647700 ;
    ANTENNADIFFAREA 0.434700 ;
    PORT
      LAYER met3 ;
        RECT 0.000 217.640 4.000 218.240 ;
    END
  END mem_rdata[0]
  PIN mem_rdata[10]
    DIRECTION INPUT ;
    USE SIGNAL ;
    ANTENNAGATEAREA 0.593700 ;
    ANTENNADIFFAREA 0.434700 ;
    PORT
      LAYER met2 ;
        RECT 209.390 0.000 209.670 4.000 ;
    END
  END mem_rdata[10]
  PIN mem_rdata[11]
    DIRECTION INPUT ;
    USE SIGNAL ;
    ANTENNAGATEAREA 0.647700 ;
    ANTENNADIFFAREA 0.434700 ;
    PORT
      LAYER met2 ;
        RECT 351.070 0.000 351.350 4.000 ;
    END
  END mem_rdata[11]
  PIN mem_rdata[12]
    DIRECTION INPUT ;
    USE SIGNAL ;
    ANTENNAGATEAREA 0.647700 ;
    ANTENNADIFFAREA 0.434700 ;
    PORT
      LAYER met3 ;
        RECT 0.000 95.240 4.000 95.840 ;
    END
  END mem_rdata[12]
  PIN mem_rdata[13]
    DIRECTION INPUT ;
    USE SIGNAL ;
    ANTENNAGATEAREA 0.593700 ;
    ANTENNADIFFAREA 0.434700 ;
    PORT
      LAYER met2 ;
        RECT 87.030 402.130 87.310 406.130 ;
    END
  END mem_rdata[13]
  PIN mem_rdata[14]
    DIRECTION INPUT ;
    USE SIGNAL ;
    ANTENNAGATEAREA 0.647700 ;
    ANTENNADIFFAREA 0.434700 ;
    PORT
      LAYER met2 ;
        RECT 273.790 0.000 274.070 4.000 ;
    END
  END mem_rdata[14]
  PIN mem_rdata[15]
    DIRECTION INPUT ;
    USE SIGNAL ;
    ANTENNAGATEAREA 0.647700 ;
    ANTENNADIFFAREA 0.434700 ;
    PORT
      LAYER met3 ;
        RECT 0.000 302.640 4.000 303.240 ;
    END
  END mem_rdata[15]
  PIN mem_rdata[16]
    DIRECTION INPUT ;
    USE SIGNAL ;
    ANTENNAGATEAREA 0.647700 ;
    ANTENNADIFFAREA 0.434700 ;
    PORT
      LAYER met2 ;
        RECT 144.990 0.000 145.270 4.000 ;
    END
  END mem_rdata[16]
  PIN mem_rdata[17]
    DIRECTION INPUT ;
    USE SIGNAL ;
    ANTENNAGATEAREA 0.647700 ;
    ANTENNADIFFAREA 0.434700 ;
    PORT
      LAYER met3 ;
        RECT 391.410 153.040 395.410 153.640 ;
    END
  END mem_rdata[17]
  PIN mem_rdata[18]
    DIRECTION INPUT ;
    USE SIGNAL ;
    ANTENNAGATEAREA 0.593700 ;
    ANTENNADIFFAREA 0.434700 ;
    PORT
      LAYER met2 ;
        RECT 70.930 402.130 71.210 406.130 ;
    END
  END mem_rdata[18]
  PIN mem_rdata[19]
    DIRECTION INPUT ;
    USE SIGNAL ;
    ANTENNAGATEAREA 0.647700 ;
    ANTENNADIFFAREA 0.434700 ;
    PORT
      LAYER met2 ;
        RECT 199.730 402.130 200.010 406.130 ;
    END
  END mem_rdata[19]
  PIN mem_rdata[1]
    DIRECTION INPUT ;
    USE SIGNAL ;
    ANTENNAGATEAREA 0.647700 ;
    ANTENNADIFFAREA 0.434700 ;
    PORT
      LAYER met2 ;
        RECT 206.170 402.130 206.450 406.130 ;
    END
  END mem_rdata[1]
  PIN mem_rdata[20]
    DIRECTION INPUT ;
    USE SIGNAL ;
    ANTENNAGATEAREA 0.682200 ;
    ANTENNADIFFAREA 0.434700 ;
    PORT
      LAYER met3 ;
        RECT 391.410 319.640 395.410 320.240 ;
    END
  END mem_rdata[20]
  PIN mem_rdata[21]
    DIRECTION INPUT ;
    USE SIGNAL ;
    ANTENNAGATEAREA 0.647700 ;
    ANTENNADIFFAREA 0.434700 ;
    PORT
      LAYER met2 ;
        RECT 157.870 402.130 158.150 406.130 ;
    END
  END mem_rdata[21]
  PIN mem_rdata[22]
    DIRECTION INPUT ;
    USE SIGNAL ;
    ANTENNAGATEAREA 0.593700 ;
    ANTENNADIFFAREA 0.434700 ;
    PORT
      LAYER met3 ;
        RECT 0.000 159.840 4.000 160.440 ;
    END
  END mem_rdata[22]
  PIN mem_rdata[23]
    DIRECTION INPUT ;
    USE SIGNAL ;
    ANTENNAGATEAREA 0.647700 ;
    ANTENNADIFFAREA 0.434700 ;
    PORT
      LAYER met2 ;
        RECT 193.290 402.130 193.570 406.130 ;
    END
  END mem_rdata[23]
  PIN mem_rdata[24]
    DIRECTION INPUT ;
    USE SIGNAL ;
    ANTENNAGATEAREA 0.682200 ;
    ANTENNADIFFAREA 0.434700 ;
    PORT
      LAYER met2 ;
        RECT 318.870 402.130 319.150 406.130 ;
    END
  END mem_rdata[24]
  PIN mem_rdata[25]
    DIRECTION INPUT ;
    USE SIGNAL ;
    ANTENNAGATEAREA 0.647700 ;
    ANTENNADIFFAREA 0.434700 ;
    PORT
      LAYER met3 ;
        RECT 0.000 23.840 4.000 24.440 ;
    END
  END mem_rdata[25]
  PIN mem_rdata[26]
    DIRECTION INPUT ;
    USE SIGNAL ;
    ANTENNAGATEAREA 0.647700 ;
    ANTENNADIFFAREA 0.434700 ;
    PORT
      LAYER met2 ;
        RECT 112.790 0.000 113.070 4.000 ;
    END
  END mem_rdata[26]
  PIN mem_rdata[27]
    DIRECTION INPUT ;
    USE SIGNAL ;
    ANTENNAGATEAREA 0.682200 ;
    ANTENNADIFFAREA 0.434700 ;
    PORT
      LAYER met2 ;
        RECT 293.110 402.130 293.390 406.130 ;
    END
  END mem_rdata[27]
  PIN mem_rdata[28]
    DIRECTION INPUT ;
    USE SIGNAL ;
    ANTENNAGATEAREA 0.682200 ;
    ANTENNADIFFAREA 0.434700 ;
    PORT
      LAYER met2 ;
        RECT 206.170 0.000 206.450 4.000 ;
    END
  END mem_rdata[28]
  PIN mem_rdata[29]
    DIRECTION INPUT ;
    USE SIGNAL ;
    ANTENNAGATEAREA 0.682200 ;
    ANTENNADIFFAREA 0.434700 ;
    PORT
      LAYER met2 ;
        RECT 351.070 402.130 351.350 406.130 ;
    END
  END mem_rdata[29]
  PIN mem_rdata[2]
    DIRECTION INPUT ;
    USE SIGNAL ;
    ANTENNAGATEAREA 0.647700 ;
    ANTENNADIFFAREA 0.434700 ;
    PORT
      LAYER met2 ;
        RECT 51.610 0.000 51.890 4.000 ;
    END
  END mem_rdata[2]
  PIN mem_rdata[30]
    DIRECTION INPUT ;
    USE SIGNAL ;
    ANTENNAGATEAREA 0.647700 ;
    ANTENNADIFFAREA 0.434700 ;
    PORT
      LAYER met3 ;
        RECT 0.000 54.440 4.000 55.040 ;
    END
  END mem_rdata[30]
  PIN mem_rdata[31]
    DIRECTION INPUT ;
    USE SIGNAL ;
    ANTENNAGATEAREA 0.647700 ;
    ANTENNADIFFAREA 0.434700 ;
    PORT
      LAYER met2 ;
        RECT 167.530 0.000 167.810 4.000 ;
    END
  END mem_rdata[31]
  PIN mem_rdata[3]
    DIRECTION INPUT ;
    USE SIGNAL ;
    ANTENNAGATEAREA 0.647700 ;
    ANTENNADIFFAREA 0.434700 ;
    PORT
      LAYER met3 ;
        RECT 0.000 74.840 4.000 75.440 ;
    END
  END mem_rdata[3]
  PIN mem_rdata[4]
    DIRECTION INPUT ;
    USE SIGNAL ;
    ANTENNAGATEAREA 0.647700 ;
    ANTENNADIFFAREA 0.434700 ;
    PORT
      LAYER met3 ;
        RECT 0.000 166.640 4.000 167.240 ;
    END
  END mem_rdata[4]
  PIN mem_rdata[5]
    DIRECTION INPUT ;
    USE SIGNAL ;
    ANTENNAGATEAREA 0.647700 ;
    ANTENNADIFFAREA 0.434700 ;
    PORT
      LAYER met2 ;
        RECT 144.990 402.130 145.270 406.130 ;
    END
  END mem_rdata[5]
  PIN mem_rdata[6]
    DIRECTION INPUT ;
    USE SIGNAL ;
    ANTENNAGATEAREA 0.593700 ;
    ANTENNADIFFAREA 0.434700 ;
    PORT
      LAYER met3 ;
        RECT 0.000 312.840 4.000 313.440 ;
    END
  END mem_rdata[6]
  PIN mem_rdata[7]
    DIRECTION INPUT ;
    USE SIGNAL ;
    ANTENNAGATEAREA 0.647700 ;
    ANTENNADIFFAREA 0.434700 ;
    PORT
      LAYER met3 ;
        RECT 391.410 61.240 395.410 61.840 ;
    END
  END mem_rdata[7]
  PIN mem_rdata[8]
    DIRECTION INPUT ;
    USE SIGNAL ;
    ANTENNAGATEAREA 0.593700 ;
    ANTENNADIFFAREA 0.434700 ;
    PORT
      LAYER met2 ;
        RECT 186.850 0.000 187.130 4.000 ;
    END
  END mem_rdata[8]
  PIN mem_rdata[9]
    DIRECTION INPUT ;
    USE SIGNAL ;
    ANTENNAGATEAREA 0.647700 ;
    ANTENNADIFFAREA 0.434700 ;
    PORT
      LAYER met2 ;
        RECT 225.490 402.130 225.770 406.130 ;
    END
  END mem_rdata[9]
  PIN mem_ready
    DIRECTION INPUT ;
    USE SIGNAL ;
    ANTENNAGATEAREA 0.631200 ;
    ANTENNADIFFAREA 0.434700 ;
    PORT
      LAYER met3 ;
        RECT 0.000 183.640 4.000 184.240 ;
    END
  END mem_ready
  PIN mem_valid
    DIRECTION OUTPUT TRISTATE ;
    USE SIGNAL ;
    ANTENNADIFFAREA 0.445500 ;
    PORT
      LAYER met3 ;
        RECT 391.410 146.240 395.410 146.840 ;
    END
  END mem_valid
  PIN mem_wdata[0]
    DIRECTION OUTPUT TRISTATE ;
    USE SIGNAL ;
    ANTENNADIFFAREA 0.795200 ;
    PORT
      LAYER met2 ;
        RECT 392.930 0.000 393.210 4.000 ;
    END
  END mem_wdata[0]
  PIN mem_wdata[10]
    DIRECTION OUTPUT TRISTATE ;
    USE SIGNAL ;
    ANTENNADIFFAREA 0.795200 ;
    PORT
      LAYER met2 ;
        RECT 148.210 402.130 148.490 406.130 ;
    END
  END mem_wdata[10]
  PIN mem_wdata[11]
    DIRECTION OUTPUT TRISTATE ;
    USE SIGNAL ;
    ANTENNADIFFAREA 0.795200 ;
    PORT
      LAYER met3 ;
        RECT 0.000 119.040 4.000 119.640 ;
    END
  END mem_wdata[11]
  PIN mem_wdata[12]
    DIRECTION OUTPUT TRISTATE ;
    USE SIGNAL ;
    ANTENNADIFFAREA 0.795200 ;
    PORT
      LAYER met2 ;
        RECT 41.950 402.130 42.230 406.130 ;
    END
  END mem_wdata[12]
  PIN mem_wdata[13]
    DIRECTION OUTPUT TRISTATE ;
    USE SIGNAL ;
    ANTENNADIFFAREA 0.795200 ;
    PORT
      LAYER met3 ;
        RECT 0.000 64.640 4.000 65.240 ;
    END
  END mem_wdata[13]
  PIN mem_wdata[14]
    DIRECTION OUTPUT TRISTATE ;
    USE SIGNAL ;
    ANTENNADIFFAREA 0.445500 ;
    PORT
      LAYER met3 ;
        RECT 391.410 333.240 395.410 333.840 ;
    END
  END mem_wdata[14]
  PIN mem_wdata[15]
    DIRECTION OUTPUT TRISTATE ;
    USE SIGNAL ;
    ANTENNADIFFAREA 0.795200 ;
    PORT
      LAYER met2 ;
        RECT 22.630 0.000 22.910 4.000 ;
    END
  END mem_wdata[15]
  PIN mem_wdata[16]
    DIRECTION OUTPUT TRISTATE ;
    USE SIGNAL ;
    ANTENNADIFFAREA 0.795200 ;
    PORT
      LAYER met2 ;
        RECT 157.870 0.000 158.150 4.000 ;
    END
  END mem_wdata[16]
  PIN mem_wdata[17]
    DIRECTION OUTPUT TRISTATE ;
    USE SIGNAL ;
    ANTENNADIFFAREA 0.795200 ;
    PORT
      LAYER met3 ;
        RECT 0.000 261.840 4.000 262.440 ;
    END
  END mem_wdata[17]
  PIN mem_wdata[18]
    DIRECTION OUTPUT TRISTATE ;
    USE SIGNAL ;
    ANTENNADIFFAREA 0.795200 ;
    PORT
      LAYER met2 ;
        RECT 354.290 0.000 354.570 4.000 ;
    END
  END mem_wdata[18]
  PIN mem_wdata[19]
    DIRECTION OUTPUT TRISTATE ;
    USE SIGNAL ;
    ANTENNADIFFAREA 0.795200 ;
    PORT
      LAYER met3 ;
        RECT 0.000 295.840 4.000 296.440 ;
    END
  END mem_wdata[19]
  PIN mem_wdata[1]
    DIRECTION OUTPUT TRISTATE ;
    USE SIGNAL ;
    ANTENNADIFFAREA 0.795200 ;
    PORT
      LAYER met2 ;
        RECT 248.030 402.130 248.310 406.130 ;
    END
  END mem_wdata[1]
  PIN mem_wdata[20]
    DIRECTION OUTPUT TRISTATE ;
    USE SIGNAL ;
    ANTENNADIFFAREA 0.795200 ;
    PORT
      LAYER met2 ;
        RECT 347.850 0.000 348.130 4.000 ;
    END
  END mem_wdata[20]
  PIN mem_wdata[21]
    DIRECTION OUTPUT TRISTATE ;
    USE SIGNAL ;
    ANTENNADIFFAREA 0.795200 ;
    PORT
      LAYER met2 ;
        RECT 235.150 402.130 235.430 406.130 ;
    END
  END mem_wdata[21]
  PIN mem_wdata[22]
    DIRECTION OUTPUT TRISTATE ;
    USE SIGNAL ;
    ANTENNADIFFAREA 0.445500 ;
    PORT
      LAYER met3 ;
        RECT 391.410 37.440 395.410 38.040 ;
    END
  END mem_wdata[22]
  PIN mem_wdata[23]
    DIRECTION OUTPUT TRISTATE ;
    USE SIGNAL ;
    ANTENNADIFFAREA 0.795200 ;
    PORT
      LAYER met3 ;
        RECT 0.000 153.040 4.000 153.640 ;
    END
  END mem_wdata[23]
  PIN mem_wdata[24]
    DIRECTION OUTPUT TRISTATE ;
    USE SIGNAL ;
    ANTENNADIFFAREA 0.795200 ;
    PORT
      LAYER met3 ;
        RECT 0.000 156.440 4.000 157.040 ;
    END
  END mem_wdata[24]
  PIN mem_wdata[25]
    DIRECTION OUTPUT TRISTATE ;
    USE SIGNAL ;
    ANTENNADIFFAREA 0.795200 ;
    PORT
      LAYER met3 ;
        RECT 0.000 346.840 4.000 347.440 ;
    END
  END mem_wdata[25]
  PIN mem_wdata[26]
    DIRECTION OUTPUT TRISTATE ;
    USE SIGNAL ;
    ANTENNADIFFAREA 0.445500 ;
    PORT
      LAYER met3 ;
        RECT 391.410 268.640 395.410 269.240 ;
    END
  END mem_wdata[26]
  PIN mem_wdata[27]
    DIRECTION OUTPUT TRISTATE ;
    USE SIGNAL ;
    ANTENNADIFFAREA 0.795200 ;
    PORT
      LAYER met2 ;
        RECT 177.190 402.130 177.470 406.130 ;
    END
  END mem_wdata[27]
  PIN mem_wdata[28]
    DIRECTION OUTPUT TRISTATE ;
    USE SIGNAL ;
    ANTENNADIFFAREA 0.795200 ;
    PORT
      LAYER met3 ;
        RECT 0.000 353.640 4.000 354.240 ;
    END
  END mem_wdata[28]
  PIN mem_wdata[29]
    DIRECTION OUTPUT TRISTATE ;
    USE SIGNAL ;
    ANTENNADIFFAREA 0.795200 ;
    PORT
      LAYER met2 ;
        RECT 312.430 402.130 312.710 406.130 ;
    END
  END mem_wdata[29]
  PIN mem_wdata[2]
    DIRECTION OUTPUT TRISTATE ;
    USE SIGNAL ;
    ANTENNADIFFAREA 0.795200 ;
    PORT
      LAYER met3 ;
        RECT 0.000 391.040 4.000 391.640 ;
    END
  END mem_wdata[2]
  PIN mem_wdata[30]
    DIRECTION OUTPUT TRISTATE ;
    USE SIGNAL ;
    ANTENNADIFFAREA 0.795200 ;
    PORT
      LAYER met3 ;
        RECT 0.000 282.240 4.000 282.840 ;
    END
  END mem_wdata[30]
  PIN mem_wdata[31]
    DIRECTION OUTPUT TRISTATE ;
    USE SIGNAL ;
    ANTENNADIFFAREA 0.795200 ;
    PORT
      LAYER met3 ;
        RECT 0.000 333.240 4.000 333.840 ;
    END
  END mem_wdata[31]
  PIN mem_wdata[3]
    DIRECTION OUTPUT TRISTATE ;
    USE SIGNAL ;
    ANTENNADIFFAREA 0.795200 ;
    PORT
      LAYER met3 ;
        RECT 0.000 207.440 4.000 208.040 ;
    END
  END mem_wdata[3]
  PIN mem_wdata[4]
    DIRECTION OUTPUT TRISTATE ;
    USE SIGNAL ;
    ANTENNADIFFAREA 0.795200 ;
    PORT
      LAYER met2 ;
        RECT 103.130 0.000 103.410 4.000 ;
    END
  END mem_wdata[4]
  PIN mem_wdata[5]
    DIRECTION OUTPUT TRISTATE ;
    USE SIGNAL ;
    ANTENNADIFFAREA 0.795200 ;
    PORT
      LAYER met2 ;
        RECT 334.970 0.000 335.250 4.000 ;
    END
  END mem_wdata[5]
  PIN mem_wdata[6]
    DIRECTION OUTPUT TRISTATE ;
    USE SIGNAL ;
    ANTENNADIFFAREA 0.445500 ;
    PORT
      LAYER met3 ;
        RECT 391.410 20.440 395.410 21.040 ;
    END
  END mem_wdata[6]
  PIN mem_wdata[7]
    DIRECTION OUTPUT TRISTATE ;
    USE SIGNAL ;
    ANTENNADIFFAREA 0.795200 ;
    PORT
      LAYER met3 ;
        RECT 0.000 289.040 4.000 289.640 ;
    END
  END mem_wdata[7]
  PIN mem_wdata[8]
    DIRECTION OUTPUT TRISTATE ;
    USE SIGNAL ;
    ANTENNADIFFAREA 0.795200 ;
    PORT
      LAYER met2 ;
        RECT 389.710 402.130 389.990 406.130 ;
    END
  END mem_wdata[8]
  PIN mem_wdata[9]
    DIRECTION OUTPUT TRISTATE ;
    USE SIGNAL ;
    ANTENNADIFFAREA 0.795200 ;
    PORT
      LAYER met2 ;
        RECT 244.810 0.000 245.090 4.000 ;
    END
  END mem_wdata[9]
  PIN mem_wstrb[0]
    DIRECTION OUTPUT TRISTATE ;
    USE SIGNAL ;
    ANTENNADIFFAREA 0.795200 ;
    PORT
      LAYER met3 ;
        RECT 391.410 183.640 395.410 184.240 ;
    END
  END mem_wstrb[0]
  PIN mem_wstrb[1]
    DIRECTION OUTPUT TRISTATE ;
    USE SIGNAL ;
    ANTENNADIFFAREA 0.795200 ;
    PORT
      LAYER met3 ;
        RECT 391.410 142.840 395.410 143.440 ;
    END
  END mem_wstrb[1]
  PIN mem_wstrb[2]
    DIRECTION OUTPUT TRISTATE ;
    USE SIGNAL ;
    ANTENNADIFFAREA 0.795200 ;
    PORT
      LAYER met3 ;
        RECT 391.410 275.440 395.410 276.040 ;
    END
  END mem_wstrb[2]
  PIN mem_wstrb[3]
    DIRECTION OUTPUT TRISTATE ;
    USE SIGNAL ;
    ANTENNADIFFAREA 0.795200 ;
    PORT
      LAYER met3 ;
        RECT 391.410 217.640 395.410 218.240 ;
    END
  END mem_wstrb[3]
  PIN pcpi_insn[0]
    DIRECTION OUTPUT TRISTATE ;
    USE SIGNAL ;
    PORT
      LAYER met2 ;
        RECT 12.970 402.130 13.250 406.130 ;
    END
  END pcpi_insn[0]
  PIN pcpi_insn[10]
    DIRECTION OUTPUT TRISTATE ;
    USE SIGNAL ;
    PORT
      LAYER met3 ;
        RECT 391.410 227.840 395.410 228.440 ;
    END
  END pcpi_insn[10]
  PIN pcpi_insn[11]
    DIRECTION OUTPUT TRISTATE ;
    USE SIGNAL ;
    PORT
      LAYER met3 ;
        RECT 0.000 13.640 4.000 14.240 ;
    END
  END pcpi_insn[11]
  PIN pcpi_insn[12]
    DIRECTION OUTPUT TRISTATE ;
    USE SIGNAL ;
    PORT
      LAYER met2 ;
        RECT 338.190 0.000 338.470 4.000 ;
    END
  END pcpi_insn[12]
  PIN pcpi_insn[13]
    DIRECTION OUTPUT TRISTATE ;
    USE SIGNAL ;
    PORT
      LAYER met2 ;
        RECT 54.830 0.000 55.110 4.000 ;
    END
  END pcpi_insn[13]
  PIN pcpi_insn[14]
    DIRECTION OUTPUT TRISTATE ;
    USE SIGNAL ;
    PORT
      LAYER met3 ;
        RECT 0.000 51.040 4.000 51.640 ;
    END
  END pcpi_insn[14]
  PIN pcpi_insn[15]
    DIRECTION OUTPUT TRISTATE ;
    USE SIGNAL ;
    PORT
      LAYER met2 ;
        RECT 35.510 402.130 35.790 406.130 ;
    END
  END pcpi_insn[15]
  PIN pcpi_insn[16]
    DIRECTION OUTPUT TRISTATE ;
    USE SIGNAL ;
    PORT
      LAYER met3 ;
        RECT 391.410 23.840 395.410 24.440 ;
    END
  END pcpi_insn[16]
  PIN pcpi_insn[17]
    DIRECTION OUTPUT TRISTATE ;
    USE SIGNAL ;
    PORT
      LAYER met3 ;
        RECT 0.000 272.040 4.000 272.640 ;
    END
  END pcpi_insn[17]
  PIN pcpi_insn[18]
    DIRECTION OUTPUT TRISTATE ;
    USE SIGNAL ;
    PORT
      LAYER met2 ;
        RECT 373.610 402.130 373.890 406.130 ;
    END
  END pcpi_insn[18]
  PIN pcpi_insn[19]
    DIRECTION OUTPUT TRISTATE ;
    USE SIGNAL ;
    PORT
      LAYER met2 ;
        RECT 173.970 402.130 174.250 406.130 ;
    END
  END pcpi_insn[19]
  PIN pcpi_insn[1]
    DIRECTION OUTPUT TRISTATE ;
    USE SIGNAL ;
    PORT
      LAYER met2 ;
        RECT 305.990 402.130 306.270 406.130 ;
    END
  END pcpi_insn[1]
  PIN pcpi_insn[20]
    DIRECTION OUTPUT TRISTATE ;
    USE SIGNAL ;
    PORT
      LAYER met2 ;
        RECT 109.570 0.000 109.850 4.000 ;
    END
  END pcpi_insn[20]
  PIN pcpi_insn[21]
    DIRECTION OUTPUT TRISTATE ;
    USE SIGNAL ;
    PORT
      LAYER met3 ;
        RECT 0.000 231.240 4.000 231.840 ;
    END
  END pcpi_insn[21]
  PIN pcpi_insn[22]
    DIRECTION OUTPUT TRISTATE ;
    USE SIGNAL ;
    PORT
      LAYER met2 ;
        RECT 341.410 0.000 341.690 4.000 ;
    END
  END pcpi_insn[22]
  PIN pcpi_insn[23]
    DIRECTION OUTPUT TRISTATE ;
    USE SIGNAL ;
    PORT
      LAYER met2 ;
        RECT 277.010 402.130 277.290 406.130 ;
    END
  END pcpi_insn[23]
  PIN pcpi_insn[24]
    DIRECTION OUTPUT TRISTATE ;
    USE SIGNAL ;
    PORT
      LAYER met2 ;
        RECT 67.710 0.000 67.990 4.000 ;
    END
  END pcpi_insn[24]
  PIN pcpi_insn[25]
    DIRECTION OUTPUT TRISTATE ;
    USE SIGNAL ;
    PORT
      LAYER met3 ;
        RECT 0.000 258.440 4.000 259.040 ;
    END
  END pcpi_insn[25]
  PIN pcpi_insn[26]
    DIRECTION OUTPUT TRISTATE ;
    USE SIGNAL ;
    PORT
      LAYER met3 ;
        RECT 391.410 380.840 395.410 381.440 ;
    END
  END pcpi_insn[26]
  PIN pcpi_insn[27]
    DIRECTION OUTPUT TRISTATE ;
    USE SIGNAL ;
    PORT
      LAYER met3 ;
        RECT 391.410 401.240 395.410 401.840 ;
    END
  END pcpi_insn[27]
  PIN pcpi_insn[28]
    DIRECTION OUTPUT TRISTATE ;
    USE SIGNAL ;
    PORT
      LAYER met3 ;
        RECT 391.410 340.040 395.410 340.640 ;
    END
  END pcpi_insn[28]
  PIN pcpi_insn[29]
    DIRECTION OUTPUT TRISTATE ;
    USE SIGNAL ;
    PORT
      LAYER met2 ;
        RECT 183.630 402.130 183.910 406.130 ;
    END
  END pcpi_insn[29]
  PIN pcpi_insn[2]
    DIRECTION OUTPUT TRISTATE ;
    USE SIGNAL ;
    PORT
      LAYER met3 ;
        RECT 391.410 323.040 395.410 323.640 ;
    END
  END pcpi_insn[2]
  PIN pcpi_insn[30]
    DIRECTION OUTPUT TRISTATE ;
    USE SIGNAL ;
    PORT
      LAYER met2 ;
        RECT 196.510 0.000 196.790 4.000 ;
    END
  END pcpi_insn[30]
  PIN pcpi_insn[31]
    DIRECTION OUTPUT TRISTATE ;
    USE SIGNAL ;
    PORT
      LAYER met2 ;
        RECT 357.510 402.130 357.790 406.130 ;
    END
  END pcpi_insn[31]
  PIN pcpi_insn[3]
    DIRECTION OUTPUT TRISTATE ;
    USE SIGNAL ;
    PORT
      LAYER met2 ;
        RECT 9.750 0.000 10.030 4.000 ;
    END
  END pcpi_insn[3]
  PIN pcpi_insn[4]
    DIRECTION OUTPUT TRISTATE ;
    USE SIGNAL ;
    PORT
      LAYER met2 ;
        RECT 3.310 0.000 3.590 4.000 ;
    END
  END pcpi_insn[4]
  PIN pcpi_insn[5]
    DIRECTION OUTPUT TRISTATE ;
    USE SIGNAL ;
    PORT
      LAYER met2 ;
        RECT 64.490 402.130 64.770 406.130 ;
    END
  END pcpi_insn[5]
  PIN pcpi_insn[6]
    DIRECTION OUTPUT TRISTATE ;
    USE SIGNAL ;
    PORT
      LAYER met2 ;
        RECT 199.730 0.000 200.010 4.000 ;
    END
  END pcpi_insn[6]
  PIN pcpi_insn[7]
    DIRECTION OUTPUT TRISTATE ;
    USE SIGNAL ;
    PORT
      LAYER met3 ;
        RECT 391.410 3.440 395.410 4.040 ;
    END
  END pcpi_insn[7]
  PIN pcpi_insn[8]
    DIRECTION OUTPUT TRISTATE ;
    USE SIGNAL ;
    PORT
      LAYER met2 ;
        RECT 386.490 402.130 386.770 406.130 ;
    END
  END pcpi_insn[8]
  PIN pcpi_insn[9]
    DIRECTION OUTPUT TRISTATE ;
    USE SIGNAL ;
    PORT
      LAYER met3 ;
        RECT 0.000 132.640 4.000 133.240 ;
    END
  END pcpi_insn[9]
  PIN pcpi_rd[0]
    DIRECTION INPUT ;
    USE SIGNAL ;
    PORT
      LAYER met2 ;
        RECT 154.650 402.130 154.930 406.130 ;
    END
  END pcpi_rd[0]
  PIN pcpi_rd[10]
    DIRECTION INPUT ;
    USE SIGNAL ;
    PORT
      LAYER met3 ;
        RECT 0.000 265.240 4.000 265.840 ;
    END
  END pcpi_rd[10]
  PIN pcpi_rd[11]
    DIRECTION INPUT ;
    USE SIGNAL ;
    PORT
      LAYER met2 ;
        RECT 74.150 0.000 74.430 4.000 ;
    END
  END pcpi_rd[11]
  PIN pcpi_rd[12]
    DIRECTION INPUT ;
    USE SIGNAL ;
    PORT
      LAYER met2 ;
        RECT 170.750 0.000 171.030 4.000 ;
    END
  END pcpi_rd[12]
  PIN pcpi_rd[13]
    DIRECTION INPUT ;
    USE SIGNAL ;
    PORT
      LAYER met2 ;
        RECT 334.970 402.130 335.250 406.130 ;
    END
  END pcpi_rd[13]
  PIN pcpi_rd[14]
    DIRECTION INPUT ;
    USE SIGNAL ;
    PORT
      LAYER met3 ;
        RECT 0.000 108.840 4.000 109.440 ;
    END
  END pcpi_rd[14]
  PIN pcpi_rd[15]
    DIRECTION INPUT ;
    USE SIGNAL ;
    PORT
      LAYER met3 ;
        RECT 0.000 47.640 4.000 48.240 ;
    END
  END pcpi_rd[15]
  PIN pcpi_rd[16]
    DIRECTION INPUT ;
    USE SIGNAL ;
    PORT
      LAYER met2 ;
        RECT 289.890 0.000 290.170 4.000 ;
    END
  END pcpi_rd[16]
  PIN pcpi_rd[17]
    DIRECTION INPUT ;
    USE SIGNAL ;
    PORT
      LAYER met3 ;
        RECT 391.410 190.440 395.410 191.040 ;
    END
  END pcpi_rd[17]
  PIN pcpi_rd[18]
    DIRECTION INPUT ;
    USE SIGNAL ;
    PORT
      LAYER met3 ;
        RECT 391.410 261.840 395.410 262.440 ;
    END
  END pcpi_rd[18]
  PIN pcpi_rd[19]
    DIRECTION INPUT ;
    USE SIGNAL ;
    PORT
      LAYER met2 ;
        RECT 296.330 0.000 296.610 4.000 ;
    END
  END pcpi_rd[19]
  PIN pcpi_rd[1]
    DIRECTION INPUT ;
    USE SIGNAL ;
    PORT
      LAYER met2 ;
        RECT 135.330 402.130 135.610 406.130 ;
    END
  END pcpi_rd[1]
  PIN pcpi_rd[20]
    DIRECTION INPUT ;
    USE SIGNAL ;
    PORT
      LAYER met2 ;
        RECT 380.050 0.000 380.330 4.000 ;
    END
  END pcpi_rd[20]
  PIN pcpi_rd[21]
    DIRECTION INPUT ;
    USE SIGNAL ;
    PORT
      LAYER met3 ;
        RECT 391.410 251.640 395.410 252.240 ;
    END
  END pcpi_rd[21]
  PIN pcpi_rd[22]
    DIRECTION INPUT ;
    USE SIGNAL ;
    PORT
      LAYER met3 ;
        RECT 0.000 248.240 4.000 248.840 ;
    END
  END pcpi_rd[22]
  PIN pcpi_rd[23]
    DIRECTION INPUT ;
    USE SIGNAL ;
    PORT
      LAYER met3 ;
        RECT 391.410 200.640 395.410 201.240 ;
    END
  END pcpi_rd[23]
  PIN pcpi_rd[24]
    DIRECTION INPUT ;
    USE SIGNAL ;
    PORT
      LAYER met3 ;
        RECT 0.000 306.040 4.000 306.640 ;
    END
  END pcpi_rd[24]
  PIN pcpi_rd[25]
    DIRECTION INPUT ;
    USE SIGNAL ;
    PORT
      LAYER met2 ;
        RECT 354.290 402.130 354.570 406.130 ;
    END
  END pcpi_rd[25]
  PIN pcpi_rd[26]
    DIRECTION INPUT ;
    USE SIGNAL ;
    PORT
      LAYER met3 ;
        RECT 391.410 34.040 395.410 34.640 ;
    END
  END pcpi_rd[26]
  PIN pcpi_rd[27]
    DIRECTION INPUT ;
    USE SIGNAL ;
    PORT
      LAYER met2 ;
        RECT 244.810 402.130 245.090 406.130 ;
    END
  END pcpi_rd[27]
  PIN pcpi_rd[28]
    DIRECTION INPUT ;
    USE SIGNAL ;
    PORT
      LAYER met2 ;
        RECT 357.510 0.000 357.790 4.000 ;
    END
  END pcpi_rd[28]
  PIN pcpi_rd[29]
    DIRECTION INPUT ;
    USE SIGNAL ;
    PORT
      LAYER met2 ;
        RECT 106.350 402.130 106.630 406.130 ;
    END
  END pcpi_rd[29]
  PIN pcpi_rd[2]
    DIRECTION INPUT ;
    USE SIGNAL ;
    PORT
      LAYER met2 ;
        RECT 48.390 0.000 48.670 4.000 ;
    END
  END pcpi_rd[2]
  PIN pcpi_rd[30]
    DIRECTION INPUT ;
    USE SIGNAL ;
    PORT
      LAYER met3 ;
        RECT 0.000 3.440 4.000 4.040 ;
    END
  END pcpi_rd[30]
  PIN pcpi_rd[31]
    DIRECTION INPUT ;
    USE SIGNAL ;
    PORT
      LAYER met3 ;
        RECT 0.000 397.840 4.000 398.440 ;
    END
  END pcpi_rd[31]
  PIN pcpi_rd[3]
    DIRECTION INPUT ;
    USE SIGNAL ;
    PORT
      LAYER met3 ;
        RECT 391.410 258.440 395.410 259.040 ;
    END
  END pcpi_rd[3]
  PIN pcpi_rd[4]
    DIRECTION INPUT ;
    USE SIGNAL ;
    PORT
      LAYER met2 ;
        RECT 96.690 0.000 96.970 4.000 ;
    END
  END pcpi_rd[4]
  PIN pcpi_rd[5]
    DIRECTION INPUT ;
    USE SIGNAL ;
    PORT
      LAYER met2 ;
        RECT 370.390 0.000 370.670 4.000 ;
    END
  END pcpi_rd[5]
  PIN pcpi_rd[6]
    DIRECTION INPUT ;
    USE SIGNAL ;
    PORT
      LAYER met2 ;
        RECT 125.670 402.130 125.950 406.130 ;
    END
  END pcpi_rd[6]
  PIN pcpi_rd[7]
    DIRECTION INPUT ;
    USE SIGNAL ;
    PORT
      LAYER met2 ;
        RECT 341.410 402.130 341.690 406.130 ;
    END
  END pcpi_rd[7]
  PIN pcpi_rd[8]
    DIRECTION INPUT ;
    USE SIGNAL ;
    PORT
      LAYER met3 ;
        RECT 391.410 302.640 395.410 303.240 ;
    END
  END pcpi_rd[8]
  PIN pcpi_rd[9]
    DIRECTION INPUT ;
    USE SIGNAL ;
    PORT
      LAYER met2 ;
        RECT 109.570 402.130 109.850 406.130 ;
    END
  END pcpi_rd[9]
  PIN pcpi_ready
    DIRECTION INPUT ;
    USE SIGNAL ;
    PORT
      LAYER met3 ;
        RECT 0.000 57.840 4.000 58.440 ;
    END
  END pcpi_ready
  PIN pcpi_rs1[0]
    DIRECTION OUTPUT TRISTATE ;
    USE SIGNAL ;
    ANTENNADIFFAREA 0.795200 ;
    PORT
      LAYER met3 ;
        RECT 391.410 64.640 395.410 65.240 ;
    END
  END pcpi_rs1[0]
  PIN pcpi_rs1[10]
    DIRECTION OUTPUT TRISTATE ;
    USE SIGNAL ;
    ANTENNADIFFAREA 0.795200 ;
    PORT
      LAYER met2 ;
        RECT 83.810 402.130 84.090 406.130 ;
    END
  END pcpi_rs1[10]
  PIN pcpi_rs1[11]
    DIRECTION OUTPUT TRISTATE ;
    USE SIGNAL ;
    ANTENNADIFFAREA 0.795200 ;
    PORT
      LAYER met3 ;
        RECT 391.410 132.640 395.410 133.240 ;
    END
  END pcpi_rs1[11]
  PIN pcpi_rs1[12]
    DIRECTION OUTPUT TRISTATE ;
    USE SIGNAL ;
    ANTENNADIFFAREA 0.795200 ;
    PORT
      LAYER met2 ;
        RECT 270.570 402.130 270.850 406.130 ;
    END
  END pcpi_rs1[12]
  PIN pcpi_rs1[13]
    DIRECTION OUTPUT TRISTATE ;
    USE SIGNAL ;
    ANTENNADIFFAREA 0.795200 ;
    PORT
      LAYER met2 ;
        RECT 186.850 402.130 187.130 406.130 ;
    END
  END pcpi_rs1[13]
  PIN pcpi_rs1[14]
    DIRECTION OUTPUT TRISTATE ;
    USE SIGNAL ;
    ANTENNADIFFAREA 0.795200 ;
    PORT
      LAYER met2 ;
        RECT 32.290 402.130 32.570 406.130 ;
    END
  END pcpi_rs1[14]
  PIN pcpi_rs1[15]
    DIRECTION OUTPUT TRISTATE ;
    USE SIGNAL ;
    ANTENNADIFFAREA 0.795200 ;
    PORT
      LAYER met2 ;
        RECT 32.290 0.000 32.570 4.000 ;
    END
  END pcpi_rs1[15]
  PIN pcpi_rs1[16]
    DIRECTION OUTPUT TRISTATE ;
    USE SIGNAL ;
    ANTENNADIFFAREA 0.795200 ;
    PORT
      LAYER met2 ;
        RECT 215.830 0.000 216.110 4.000 ;
    END
  END pcpi_rs1[16]
  PIN pcpi_rs1[17]
    DIRECTION OUTPUT TRISTATE ;
    USE SIGNAL ;
    ANTENNADIFFAREA 0.795200 ;
    PORT
      LAYER met3 ;
        RECT 391.410 295.840 395.410 296.440 ;
    END
  END pcpi_rs1[17]
  PIN pcpi_rs1[18]
    DIRECTION OUTPUT TRISTATE ;
    USE SIGNAL ;
    ANTENNADIFFAREA 0.445500 ;
    PORT
      LAYER met3 ;
        RECT 391.410 272.040 395.410 272.640 ;
    END
  END pcpi_rs1[18]
  PIN pcpi_rs1[19]
    DIRECTION OUTPUT TRISTATE ;
    USE SIGNAL ;
    ANTENNADIFFAREA 0.795200 ;
    PORT
      LAYER met2 ;
        RECT 248.030 0.000 248.310 4.000 ;
    END
  END pcpi_rs1[19]
  PIN pcpi_rs1[1]
    DIRECTION OUTPUT TRISTATE ;
    USE SIGNAL ;
    ANTENNADIFFAREA 0.795200 ;
    PORT
      LAYER met3 ;
        RECT 391.410 238.040 395.410 238.640 ;
    END
  END pcpi_rs1[1]
  PIN pcpi_rs1[20]
    DIRECTION OUTPUT TRISTATE ;
    USE SIGNAL ;
    ANTENNADIFFAREA 0.795200 ;
    PORT
      LAYER met3 ;
        RECT 391.410 122.440 395.410 123.040 ;
    END
  END pcpi_rs1[20]
  PIN pcpi_rs1[21]
    DIRECTION OUTPUT TRISTATE ;
    USE SIGNAL ;
    ANTENNADIFFAREA 0.795200 ;
    PORT
      LAYER met2 ;
        RECT 373.610 0.000 373.890 4.000 ;
    END
  END pcpi_rs1[21]
  PIN pcpi_rs1[22]
    DIRECTION OUTPUT TRISTATE ;
    USE SIGNAL ;
    ANTENNADIFFAREA 0.795200 ;
    PORT
      LAYER met2 ;
        RECT 257.690 402.130 257.970 406.130 ;
    END
  END pcpi_rs1[22]
  PIN pcpi_rs1[23]
    DIRECTION OUTPUT TRISTATE ;
    USE SIGNAL ;
    ANTENNADIFFAREA 0.795200 ;
    PORT
      LAYER met2 ;
        RECT 370.390 402.130 370.670 406.130 ;
    END
  END pcpi_rs1[23]
  PIN pcpi_rs1[24]
    DIRECTION OUTPUT TRISTATE ;
    USE SIGNAL ;
    ANTENNADIFFAREA 0.795200 ;
    PORT
      LAYER met2 ;
        RECT 219.050 0.000 219.330 4.000 ;
    END
  END pcpi_rs1[24]
  PIN pcpi_rs1[25]
    DIRECTION OUTPUT TRISTATE ;
    USE SIGNAL ;
    ANTENNADIFFAREA 0.795200 ;
    PORT
      LAYER met2 ;
        RECT 315.650 0.000 315.930 4.000 ;
    END
  END pcpi_rs1[25]
  PIN pcpi_rs1[26]
    DIRECTION OUTPUT TRISTATE ;
    USE SIGNAL ;
    ANTENNADIFFAREA 0.795200 ;
    PORT
      LAYER met3 ;
        RECT 391.410 85.040 395.410 85.640 ;
    END
  END pcpi_rs1[26]
  PIN pcpi_rs1[27]
    DIRECTION OUTPUT TRISTATE ;
    USE SIGNAL ;
    ANTENNADIFFAREA 0.795200 ;
    PORT
      LAYER met2 ;
        RECT 54.830 402.130 55.110 406.130 ;
    END
  END pcpi_rs1[27]
  PIN pcpi_rs1[28]
    DIRECTION OUTPUT TRISTATE ;
    USE SIGNAL ;
    ANTENNADIFFAREA 0.795200 ;
    PORT
      LAYER met3 ;
        RECT 0.000 71.440 4.000 72.040 ;
    END
  END pcpi_rs1[28]
  PIN pcpi_rs1[29]
    DIRECTION OUTPUT TRISTATE ;
    USE SIGNAL ;
    ANTENNADIFFAREA 0.795200 ;
    PORT
      LAYER met2 ;
        RECT 41.950 0.000 42.230 4.000 ;
    END
  END pcpi_rs1[29]
  PIN pcpi_rs1[2]
    DIRECTION OUTPUT TRISTATE ;
    USE SIGNAL ;
    ANTENNADIFFAREA 0.795200 ;
    PORT
      LAYER met2 ;
        RECT 138.550 402.130 138.830 406.130 ;
    END
  END pcpi_rs1[2]
  PIN pcpi_rs1[30]
    DIRECTION OUTPUT TRISTATE ;
    USE SIGNAL ;
    ANTENNADIFFAREA 0.795200 ;
    PORT
      LAYER met3 ;
        RECT 0.000 146.240 4.000 146.840 ;
    END
  END pcpi_rs1[30]
  PIN pcpi_rs1[31]
    DIRECTION OUTPUT TRISTATE ;
    USE SIGNAL ;
    ANTENNADIFFAREA 0.445500 ;
    PORT
      LAYER met3 ;
        RECT 391.410 387.640 395.410 388.240 ;
    END
  END pcpi_rs1[31]
  PIN pcpi_rs1[3]
    DIRECTION OUTPUT TRISTATE ;
    USE SIGNAL ;
    ANTENNADIFFAREA 0.795200 ;
    PORT
      LAYER met2 ;
        RECT 151.430 0.000 151.710 4.000 ;
    END
  END pcpi_rs1[3]
  PIN pcpi_rs1[4]
    DIRECTION OUTPUT TRISTATE ;
    USE SIGNAL ;
    ANTENNADIFFAREA 0.795200 ;
    PORT
      LAYER met3 ;
        RECT 0.000 163.240 4.000 163.840 ;
    END
  END pcpi_rs1[4]
  PIN pcpi_rs1[5]
    DIRECTION OUTPUT TRISTATE ;
    USE SIGNAL ;
    ANTENNADIFFAREA 0.795200 ;
    PORT
      LAYER met3 ;
        RECT 391.410 166.640 395.410 167.240 ;
    END
  END pcpi_rs1[5]
  PIN pcpi_rs1[6]
    DIRECTION OUTPUT TRISTATE ;
    USE SIGNAL ;
    ANTENNADIFFAREA 0.795200 ;
    PORT
      LAYER met2 ;
        RECT 305.990 0.000 306.270 4.000 ;
    END
  END pcpi_rs1[6]
  PIN pcpi_rs1[7]
    DIRECTION OUTPUT TRISTATE ;
    USE SIGNAL ;
    ANTENNADIFFAREA 0.795200 ;
    PORT
      LAYER met2 ;
        RECT 309.210 402.130 309.490 406.130 ;
    END
  END pcpi_rs1[7]
  PIN pcpi_rs1[8]
    DIRECTION OUTPUT TRISTATE ;
    USE SIGNAL ;
    ANTENNADIFFAREA 0.795200 ;
    PORT
      LAYER met2 ;
        RECT 293.110 0.000 293.390 4.000 ;
    END
  END pcpi_rs1[8]
  PIN pcpi_rs1[9]
    DIRECTION OUTPUT TRISTATE ;
    USE SIGNAL ;
    ANTENNADIFFAREA 0.795200 ;
    PORT
      LAYER met3 ;
        RECT 0.000 200.640 4.000 201.240 ;
    END
  END pcpi_rs1[9]
  PIN pcpi_rs2[0]
    DIRECTION OUTPUT TRISTATE ;
    USE SIGNAL ;
    ANTENNADIFFAREA 0.795200 ;
    PORT
      LAYER met2 ;
        RECT 16.190 0.000 16.470 4.000 ;
    END
  END pcpi_rs2[0]
  PIN pcpi_rs2[10]
    DIRECTION OUTPUT TRISTATE ;
    USE SIGNAL ;
    ANTENNADIFFAREA 0.795200 ;
    PORT
      LAYER met2 ;
        RECT 389.710 0.000 389.990 4.000 ;
    END
  END pcpi_rs2[10]
  PIN pcpi_rs2[11]
    DIRECTION OUTPUT TRISTATE ;
    USE SIGNAL ;
    ANTENNADIFFAREA 0.445500 ;
    PORT
      LAYER met3 ;
        RECT 391.410 105.440 395.410 106.040 ;
    END
  END pcpi_rs2[11]
  PIN pcpi_rs2[12]
    DIRECTION OUTPUT TRISTATE ;
    USE SIGNAL ;
    ANTENNADIFFAREA 0.795200 ;
    PORT
      LAYER met2 ;
        RECT 128.890 402.130 129.170 406.130 ;
    END
  END pcpi_rs2[12]
  PIN pcpi_rs2[13]
    DIRECTION OUTPUT TRISTATE ;
    USE SIGNAL ;
    ANTENNADIFFAREA 0.795200 ;
    PORT
      LAYER met3 ;
        RECT 391.410 350.240 395.410 350.840 ;
    END
  END pcpi_rs2[13]
  PIN pcpi_rs2[14]
    DIRECTION OUTPUT TRISTATE ;
    USE SIGNAL ;
    ANTENNADIFFAREA 0.795200 ;
    PORT
      LAYER met3 ;
        RECT 0.000 323.040 4.000 323.640 ;
    END
  END pcpi_rs2[14]
  PIN pcpi_rs2[15]
    DIRECTION OUTPUT TRISTATE ;
    USE SIGNAL ;
    ANTENNADIFFAREA 0.795200 ;
    PORT
      LAYER met3 ;
        RECT 0.000 350.240 4.000 350.840 ;
    END
  END pcpi_rs2[15]
  PIN pcpi_rs2[16]
    DIRECTION OUTPUT TRISTATE ;
    USE SIGNAL ;
    ANTENNADIFFAREA 0.795200 ;
    PORT
      LAYER met3 ;
        RECT 0.000 336.640 4.000 337.240 ;
    END
  END pcpi_rs2[16]
  PIN pcpi_rs2[17]
    DIRECTION OUTPUT TRISTATE ;
    USE SIGNAL ;
    ANTENNADIFFAREA 0.795200 ;
    PORT
      LAYER met2 ;
        RECT 12.970 0.000 13.250 4.000 ;
    END
  END pcpi_rs2[17]
  PIN pcpi_rs2[18]
    DIRECTION OUTPUT TRISTATE ;
    USE SIGNAL ;
    ANTENNADIFFAREA 0.795200 ;
    PORT
      LAYER met2 ;
        RECT 83.810 0.000 84.090 4.000 ;
    END
  END pcpi_rs2[18]
  PIN pcpi_rs2[19]
    DIRECTION OUTPUT TRISTATE ;
    USE SIGNAL ;
    ANTENNADIFFAREA 0.795200 ;
    PORT
      LAYER met3 ;
        RECT 391.410 207.440 395.410 208.040 ;
    END
  END pcpi_rs2[19]
  PIN pcpi_rs2[1]
    DIRECTION OUTPUT TRISTATE ;
    USE SIGNAL ;
    ANTENNADIFFAREA 0.795200 ;
    PORT
      LAYER met2 ;
        RECT 225.490 0.000 225.770 4.000 ;
    END
  END pcpi_rs2[1]
  PIN pcpi_rs2[20]
    DIRECTION OUTPUT TRISTATE ;
    USE SIGNAL ;
    ANTENNADIFFAREA 0.795200 ;
    PORT
      LAYER met3 ;
        RECT 0.000 68.040 4.000 68.640 ;
    END
  END pcpi_rs2[20]
  PIN pcpi_rs2[21]
    DIRECTION OUTPUT TRISTATE ;
    USE SIGNAL ;
    ANTENNADIFFAREA 0.795200 ;
    PORT
      LAYER met2 ;
        RECT 367.170 402.130 367.450 406.130 ;
    END
  END pcpi_rs2[21]
  PIN pcpi_rs2[22]
    DIRECTION OUTPUT TRISTATE ;
    USE SIGNAL ;
    ANTENNADIFFAREA 0.795200 ;
    PORT
      LAYER met2 ;
        RECT 29.070 402.130 29.350 406.130 ;
    END
  END pcpi_rs2[22]
  PIN pcpi_rs2[23]
    DIRECTION OUTPUT TRISTATE ;
    USE SIGNAL ;
    ANTENNADIFFAREA 0.795200 ;
    PORT
      LAYER met2 ;
        RECT 61.270 0.000 61.550 4.000 ;
    END
  END pcpi_rs2[23]
  PIN pcpi_rs2[24]
    DIRECTION OUTPUT TRISTATE ;
    USE SIGNAL ;
    ANTENNADIFFAREA 0.795200 ;
    PORT
      LAYER met3 ;
        RECT 0.000 102.040 4.000 102.640 ;
    END
  END pcpi_rs2[24]
  PIN pcpi_rs2[25]
    DIRECTION OUTPUT TRISTATE ;
    USE SIGNAL ;
    ANTENNADIFFAREA 0.795200 ;
    PORT
      LAYER met2 ;
        RECT 376.830 402.130 377.110 406.130 ;
    END
  END pcpi_rs2[25]
  PIN pcpi_rs2[26]
    DIRECTION OUTPUT TRISTATE ;
    USE SIGNAL ;
    ANTENNADIFFAREA 0.795200 ;
    PORT
      LAYER met3 ;
        RECT 0.000 244.840 4.000 245.440 ;
    END
  END pcpi_rs2[26]
  PIN pcpi_rs2[27]
    DIRECTION OUTPUT TRISTATE ;
    USE SIGNAL ;
    ANTENNADIFFAREA 0.795200 ;
    PORT
      LAYER met3 ;
        RECT 391.410 316.240 395.410 316.840 ;
    END
  END pcpi_rs2[27]
  PIN pcpi_rs2[28]
    DIRECTION OUTPUT TRISTATE ;
    USE SIGNAL ;
    ANTENNADIFFAREA 0.795200 ;
    PORT
      LAYER met3 ;
        RECT 391.410 129.240 395.410 129.840 ;
    END
  END pcpi_rs2[28]
  PIN pcpi_rs2[29]
    DIRECTION OUTPUT TRISTATE ;
    USE SIGNAL ;
    ANTENNADIFFAREA 0.795200 ;
    PORT
      LAYER met2 ;
        RECT 270.570 0.000 270.850 4.000 ;
    END
  END pcpi_rs2[29]
  PIN pcpi_rs2[2]
    DIRECTION OUTPUT TRISTATE ;
    USE SIGNAL ;
    ANTENNADIFFAREA 0.795200 ;
    PORT
      LAYER met2 ;
        RECT 331.750 402.130 332.030 406.130 ;
    END
  END pcpi_rs2[2]
  PIN pcpi_rs2[30]
    DIRECTION OUTPUT TRISTATE ;
    USE SIGNAL ;
    ANTENNADIFFAREA 0.795200 ;
    PORT
      LAYER met2 ;
        RECT 103.130 402.130 103.410 406.130 ;
    END
  END pcpi_rs2[30]
  PIN pcpi_rs2[31]
    DIRECTION OUTPUT TRISTATE ;
    USE SIGNAL ;
    ANTENNADIFFAREA 0.795200 ;
    PORT
      LAYER met2 ;
        RECT 122.450 0.000 122.730 4.000 ;
    END
  END pcpi_rs2[31]
  PIN pcpi_rs2[3]
    DIRECTION OUTPUT TRISTATE ;
    USE SIGNAL ;
    ANTENNADIFFAREA 0.795200 ;
    PORT
      LAYER met3 ;
        RECT 391.410 241.440 395.410 242.040 ;
    END
  END pcpi_rs2[3]
  PIN pcpi_rs2[4]
    DIRECTION OUTPUT TRISTATE ;
    USE SIGNAL ;
    ANTENNADIFFAREA 0.795200 ;
    PORT
      LAYER met2 ;
        RECT 318.870 0.000 319.150 4.000 ;
    END
  END pcpi_rs2[4]
  PIN pcpi_rs2[5]
    DIRECTION OUTPUT TRISTATE ;
    USE SIGNAL ;
    ANTENNADIFFAREA 0.445500 ;
    PORT
      LAYER met3 ;
        RECT 391.410 112.240 395.410 112.840 ;
    END
  END pcpi_rs2[5]
  PIN pcpi_rs2[6]
    DIRECTION OUTPUT TRISTATE ;
    USE SIGNAL ;
    ANTENNADIFFAREA 0.795200 ;
    PORT
      LAYER met3 ;
        RECT 0.000 221.040 4.000 221.640 ;
    END
  END pcpi_rs2[6]
  PIN pcpi_rs2[7]
    DIRECTION OUTPUT TRISTATE ;
    USE SIGNAL ;
    ANTENNADIFFAREA 0.795200 ;
    PORT
      LAYER met3 ;
        RECT 391.410 6.840 395.410 7.440 ;
    END
  END pcpi_rs2[7]
  PIN pcpi_rs2[8]
    DIRECTION OUTPUT TRISTATE ;
    USE SIGNAL ;
    ANTENNADIFFAREA 0.795200 ;
    PORT
      LAYER met2 ;
        RECT 64.490 0.000 64.770 4.000 ;
    END
  END pcpi_rs2[8]
  PIN pcpi_rs2[9]
    DIRECTION OUTPUT TRISTATE ;
    USE SIGNAL ;
    ANTENNADIFFAREA 0.795200 ;
    PORT
      LAYER met2 ;
        RECT 193.290 0.000 193.570 4.000 ;
    END
  END pcpi_rs2[9]
  PIN pcpi_valid
    DIRECTION OUTPUT TRISTATE ;
    USE SIGNAL ;
    PORT
      LAYER met3 ;
        RECT 391.410 173.440 395.410 174.040 ;
    END
  END pcpi_valid
  PIN pcpi_wait
    DIRECTION INPUT ;
    USE SIGNAL ;
    PORT
      LAYER met2 ;
        RECT 315.650 402.130 315.930 406.130 ;
    END
  END pcpi_wait
  PIN pcpi_wr
    DIRECTION INPUT ;
    USE SIGNAL ;
    PORT
      LAYER met3 ;
        RECT 391.410 363.840 395.410 364.440 ;
    END
  END pcpi_wr
  PIN resetn
    DIRECTION INPUT ;
    USE SIGNAL ;
    ANTENNAGATEAREA 0.929700 ;
    ANTENNADIFFAREA 0.434700 ;
    PORT
      LAYER met3 ;
        RECT 391.410 17.040 395.410 17.640 ;
    END
  END resetn
  PIN trace_data[0]
    DIRECTION OUTPUT TRISTATE ;
    USE SIGNAL ;
    PORT
      LAYER met3 ;
        RECT 0.000 81.640 4.000 82.240 ;
    END
  END trace_data[0]
  PIN trace_data[10]
    DIRECTION OUTPUT TRISTATE ;
    USE SIGNAL ;
    PORT
      LAYER met3 ;
        RECT 391.410 231.240 395.410 231.840 ;
    END
  END trace_data[10]
  PIN trace_data[11]
    DIRECTION OUTPUT TRISTATE ;
    USE SIGNAL ;
    PORT
      LAYER met2 ;
        RECT 6.530 0.000 6.810 4.000 ;
    END
  END trace_data[11]
  PIN trace_data[12]
    DIRECTION OUTPUT TRISTATE ;
    USE SIGNAL ;
    PORT
      LAYER met3 ;
        RECT 391.410 370.640 395.410 371.240 ;
    END
  END trace_data[12]
  PIN trace_data[13]
    DIRECTION OUTPUT TRISTATE ;
    USE SIGNAL ;
    PORT
      LAYER met2 ;
        RECT 299.550 402.130 299.830 406.130 ;
    END
  END trace_data[13]
  PIN trace_data[14]
    DIRECTION OUTPUT TRISTATE ;
    USE SIGNAL ;
    PORT
      LAYER met3 ;
        RECT 391.410 40.840 395.410 41.440 ;
    END
  END trace_data[14]
  PIN trace_data[15]
    DIRECTION OUTPUT TRISTATE ;
    USE SIGNAL ;
    PORT
      LAYER met2 ;
        RECT 286.670 402.130 286.950 406.130 ;
    END
  END trace_data[15]
  PIN trace_data[16]
    DIRECTION OUTPUT TRISTATE ;
    USE SIGNAL ;
    PORT
      LAYER met3 ;
        RECT 0.000 115.640 4.000 116.240 ;
    END
  END trace_data[16]
  PIN trace_data[17]
    DIRECTION OUTPUT TRISTATE ;
    USE SIGNAL ;
    PORT
      LAYER met3 ;
        RECT 0.000 129.240 4.000 129.840 ;
    END
  END trace_data[17]
  PIN trace_data[18]
    DIRECTION OUTPUT TRISTATE ;
    USE SIGNAL ;
    PORT
      LAYER met2 ;
        RECT 260.910 0.000 261.190 4.000 ;
    END
  END trace_data[18]
  PIN trace_data[19]
    DIRECTION OUTPUT TRISTATE ;
    USE SIGNAL ;
    PORT
      LAYER met2 ;
        RECT 0.090 0.000 0.370 4.000 ;
    END
  END trace_data[19]
  PIN trace_data[1]
    DIRECTION OUTPUT TRISTATE ;
    USE SIGNAL ;
    PORT
      LAYER met2 ;
        RECT 309.210 0.000 309.490 4.000 ;
    END
  END trace_data[1]
  PIN trace_data[20]
    DIRECTION OUTPUT TRISTATE ;
    USE SIGNAL ;
    PORT
      LAYER met3 ;
        RECT 0.000 197.240 4.000 197.840 ;
    END
  END trace_data[20]
  PIN trace_data[21]
    DIRECTION OUTPUT TRISTATE ;
    USE SIGNAL ;
    PORT
      LAYER met3 ;
        RECT 0.000 357.040 4.000 357.640 ;
    END
  END trace_data[21]
  PIN trace_data[22]
    DIRECTION OUTPUT TRISTATE ;
    USE SIGNAL ;
    PORT
      LAYER met2 ;
        RECT 112.790 402.130 113.070 406.130 ;
    END
  END trace_data[22]
  PIN trace_data[23]
    DIRECTION OUTPUT TRISTATE ;
    USE SIGNAL ;
    PORT
      LAYER met3 ;
        RECT 0.000 136.040 4.000 136.640 ;
    END
  END trace_data[23]
  PIN trace_data[24]
    DIRECTION OUTPUT TRISTATE ;
    USE SIGNAL ;
    PORT
      LAYER met2 ;
        RECT 77.370 0.000 77.650 4.000 ;
    END
  END trace_data[24]
  PIN trace_data[25]
    DIRECTION OUTPUT TRISTATE ;
    USE SIGNAL ;
    PORT
      LAYER met2 ;
        RECT 29.070 0.000 29.350 4.000 ;
    END
  END trace_data[25]
  PIN trace_data[26]
    DIRECTION OUTPUT TRISTATE ;
    USE SIGNAL ;
    PORT
      LAYER met2 ;
        RECT 209.390 402.130 209.670 406.130 ;
    END
  END trace_data[26]
  PIN trace_data[27]
    DIRECTION OUTPUT TRISTATE ;
    USE SIGNAL ;
    PORT
      LAYER met2 ;
        RECT 122.450 402.130 122.730 406.130 ;
    END
  END trace_data[27]
  PIN trace_data[28]
    DIRECTION OUTPUT TRISTATE ;
    USE SIGNAL ;
    PORT
      LAYER met2 ;
        RECT 212.610 0.000 212.890 4.000 ;
    END
  END trace_data[28]
  PIN trace_data[29]
    DIRECTION OUTPUT TRISTATE ;
    USE SIGNAL ;
    PORT
      LAYER met2 ;
        RECT 273.790 402.130 274.070 406.130 ;
    END
  END trace_data[29]
  PIN trace_data[2]
    DIRECTION OUTPUT TRISTATE ;
    USE SIGNAL ;
    PORT
      LAYER met3 ;
        RECT 391.410 108.840 395.410 109.440 ;
    END
  END trace_data[2]
  PIN trace_data[30]
    DIRECTION OUTPUT TRISTATE ;
    USE SIGNAL ;
    PORT
      LAYER met3 ;
        RECT 0.000 268.640 4.000 269.240 ;
    END
  END trace_data[30]
  PIN trace_data[31]
    DIRECTION OUTPUT TRISTATE ;
    USE SIGNAL ;
    PORT
      LAYER met3 ;
        RECT 391.410 312.840 395.410 313.440 ;
    END
  END trace_data[31]
  PIN trace_data[32]
    DIRECTION OUTPUT TRISTATE ;
    USE SIGNAL ;
    PORT
      LAYER met2 ;
        RECT 87.030 0.000 87.310 4.000 ;
    END
  END trace_data[32]
  PIN trace_data[33]
    DIRECTION OUTPUT TRISTATE ;
    USE SIGNAL ;
    PORT
      LAYER met2 ;
        RECT 148.210 0.000 148.490 4.000 ;
    END
  END trace_data[33]
  PIN trace_data[34]
    DIRECTION OUTPUT TRISTATE ;
    USE SIGNAL ;
    PORT
      LAYER met3 ;
        RECT 0.000 34.040 4.000 34.640 ;
    END
  END trace_data[34]
  PIN trace_data[35]
    DIRECTION OUTPUT TRISTATE ;
    USE SIGNAL ;
    PORT
      LAYER met3 ;
        RECT 391.410 299.240 395.410 299.840 ;
    END
  END trace_data[35]
  PIN trace_data[3]
    DIRECTION OUTPUT TRISTATE ;
    USE SIGNAL ;
    PORT
      LAYER met2 ;
        RECT 235.150 0.000 235.430 4.000 ;
    END
  END trace_data[3]
  PIN trace_data[4]
    DIRECTION OUTPUT TRISTATE ;
    USE SIGNAL ;
    PORT
      LAYER met2 ;
        RECT 264.130 402.130 264.410 406.130 ;
    END
  END trace_data[4]
  PIN trace_data[5]
    DIRECTION OUTPUT TRISTATE ;
    USE SIGNAL ;
    PORT
      LAYER met2 ;
        RECT 254.470 402.130 254.750 406.130 ;
    END
  END trace_data[5]
  PIN trace_data[6]
    DIRECTION OUTPUT TRISTATE ;
    USE SIGNAL ;
    PORT
      LAYER met3 ;
        RECT 0.000 380.840 4.000 381.440 ;
    END
  END trace_data[6]
  PIN trace_data[7]
    DIRECTION OUTPUT TRISTATE ;
    USE SIGNAL ;
    PORT
      LAYER met2 ;
        RECT 45.170 402.130 45.450 406.130 ;
    END
  END trace_data[7]
  PIN trace_data[8]
    DIRECTION OUTPUT TRISTATE ;
    USE SIGNAL ;
    PORT
      LAYER met2 ;
        RECT 280.230 0.000 280.510 4.000 ;
    END
  END trace_data[8]
  PIN trace_data[9]
    DIRECTION OUTPUT TRISTATE ;
    USE SIGNAL ;
    PORT
      LAYER met3 ;
        RECT 0.000 91.840 4.000 92.440 ;
    END
  END trace_data[9]
  PIN trace_valid
    DIRECTION OUTPUT TRISTATE ;
    USE SIGNAL ;
    PORT
      LAYER met3 ;
        RECT 0.000 343.440 4.000 344.040 ;
    END
  END trace_valid
  PIN trap
    DIRECTION OUTPUT TRISTATE ;
    USE SIGNAL ;
    ANTENNADIFFAREA 0.795200 ;
    PORT
      LAYER met3 ;
        RECT 391.410 197.240 395.410 197.840 ;
    END
  END trap
  OBS
      LAYER li1 ;
        RECT 5.520 10.795 389.620 394.485 ;
      LAYER met1 ;
        RECT 0.070 5.820 395.070 401.840 ;
      LAYER met2 ;
        RECT 0.650 401.850 3.030 402.290 ;
        RECT 3.870 401.850 6.250 402.290 ;
        RECT 7.090 401.850 9.470 402.290 ;
        RECT 10.310 401.850 12.690 402.290 ;
        RECT 13.530 401.850 15.910 402.290 ;
        RECT 16.750 401.850 22.350 402.290 ;
        RECT 23.190 401.850 25.570 402.290 ;
        RECT 26.410 401.850 28.790 402.290 ;
        RECT 29.630 401.850 32.010 402.290 ;
        RECT 32.850 401.850 35.230 402.290 ;
        RECT 36.070 401.850 41.670 402.290 ;
        RECT 42.510 401.850 44.890 402.290 ;
        RECT 45.730 401.850 48.110 402.290 ;
        RECT 48.950 401.850 51.330 402.290 ;
        RECT 52.170 401.850 54.550 402.290 ;
        RECT 55.390 401.850 60.990 402.290 ;
        RECT 61.830 401.850 64.210 402.290 ;
        RECT 65.050 401.850 67.430 402.290 ;
        RECT 68.270 401.850 70.650 402.290 ;
        RECT 71.490 401.850 73.870 402.290 ;
        RECT 74.710 401.850 77.090 402.290 ;
        RECT 77.930 401.850 83.530 402.290 ;
        RECT 84.370 401.850 86.750 402.290 ;
        RECT 87.590 401.850 89.970 402.290 ;
        RECT 90.810 401.850 93.190 402.290 ;
        RECT 94.030 401.850 96.410 402.290 ;
        RECT 97.250 401.850 102.850 402.290 ;
        RECT 103.690 401.850 106.070 402.290 ;
        RECT 106.910 401.850 109.290 402.290 ;
        RECT 110.130 401.850 112.510 402.290 ;
        RECT 113.350 401.850 115.730 402.290 ;
        RECT 116.570 401.850 122.170 402.290 ;
        RECT 123.010 401.850 125.390 402.290 ;
        RECT 126.230 401.850 128.610 402.290 ;
        RECT 129.450 401.850 131.830 402.290 ;
        RECT 132.670 401.850 135.050 402.290 ;
        RECT 135.890 401.850 138.270 402.290 ;
        RECT 139.110 401.850 144.710 402.290 ;
        RECT 145.550 401.850 147.930 402.290 ;
        RECT 148.770 401.850 151.150 402.290 ;
        RECT 151.990 401.850 154.370 402.290 ;
        RECT 155.210 401.850 157.590 402.290 ;
        RECT 158.430 401.850 164.030 402.290 ;
        RECT 164.870 401.850 167.250 402.290 ;
        RECT 168.090 401.850 170.470 402.290 ;
        RECT 171.310 401.850 173.690 402.290 ;
        RECT 174.530 401.850 176.910 402.290 ;
        RECT 177.750 401.850 183.350 402.290 ;
        RECT 184.190 401.850 186.570 402.290 ;
        RECT 187.410 401.850 189.790 402.290 ;
        RECT 190.630 401.850 193.010 402.290 ;
        RECT 193.850 401.850 196.230 402.290 ;
        RECT 197.070 401.850 199.450 402.290 ;
        RECT 200.290 401.850 205.890 402.290 ;
        RECT 206.730 401.850 209.110 402.290 ;
        RECT 209.950 401.850 212.330 402.290 ;
        RECT 213.170 401.850 215.550 402.290 ;
        RECT 216.390 401.850 218.770 402.290 ;
        RECT 219.610 401.850 225.210 402.290 ;
        RECT 226.050 401.850 228.430 402.290 ;
        RECT 229.270 401.850 231.650 402.290 ;
        RECT 232.490 401.850 234.870 402.290 ;
        RECT 235.710 401.850 238.090 402.290 ;
        RECT 238.930 401.850 244.530 402.290 ;
        RECT 245.370 401.850 247.750 402.290 ;
        RECT 248.590 401.850 250.970 402.290 ;
        RECT 251.810 401.850 254.190 402.290 ;
        RECT 255.030 401.850 257.410 402.290 ;
        RECT 258.250 401.850 263.850 402.290 ;
        RECT 264.690 401.850 267.070 402.290 ;
        RECT 267.910 401.850 270.290 402.290 ;
        RECT 271.130 401.850 273.510 402.290 ;
        RECT 274.350 401.850 276.730 402.290 ;
        RECT 277.570 401.850 279.950 402.290 ;
        RECT 280.790 401.850 286.390 402.290 ;
        RECT 287.230 401.850 289.610 402.290 ;
        RECT 290.450 401.850 292.830 402.290 ;
        RECT 293.670 401.850 296.050 402.290 ;
        RECT 296.890 401.850 299.270 402.290 ;
        RECT 300.110 401.850 305.710 402.290 ;
        RECT 306.550 401.850 308.930 402.290 ;
        RECT 309.770 401.850 312.150 402.290 ;
        RECT 312.990 401.850 315.370 402.290 ;
        RECT 316.210 401.850 318.590 402.290 ;
        RECT 319.430 401.850 325.030 402.290 ;
        RECT 325.870 401.850 328.250 402.290 ;
        RECT 329.090 401.850 331.470 402.290 ;
        RECT 332.310 401.850 334.690 402.290 ;
        RECT 335.530 401.850 337.910 402.290 ;
        RECT 338.750 401.850 341.130 402.290 ;
        RECT 341.970 401.850 347.570 402.290 ;
        RECT 348.410 401.850 350.790 402.290 ;
        RECT 351.630 401.850 354.010 402.290 ;
        RECT 354.850 401.850 357.230 402.290 ;
        RECT 358.070 401.850 360.450 402.290 ;
        RECT 361.290 401.850 366.890 402.290 ;
        RECT 367.730 401.850 370.110 402.290 ;
        RECT 370.950 401.850 373.330 402.290 ;
        RECT 374.170 401.850 376.550 402.290 ;
        RECT 377.390 401.850 379.770 402.290 ;
        RECT 380.610 401.850 386.210 402.290 ;
        RECT 387.050 401.850 389.430 402.290 ;
        RECT 390.270 401.850 392.650 402.290 ;
        RECT 393.490 401.850 395.050 402.290 ;
        RECT 0.090 4.280 395.050 401.850 ;
        RECT 0.650 0.155 3.030 4.280 ;
        RECT 3.870 0.155 6.250 4.280 ;
        RECT 7.090 0.155 9.470 4.280 ;
        RECT 10.310 0.155 12.690 4.280 ;
        RECT 13.530 0.155 15.910 4.280 ;
        RECT 16.750 0.155 22.350 4.280 ;
        RECT 23.190 0.155 25.570 4.280 ;
        RECT 26.410 0.155 28.790 4.280 ;
        RECT 29.630 0.155 32.010 4.280 ;
        RECT 32.850 0.155 35.230 4.280 ;
        RECT 36.070 0.155 41.670 4.280 ;
        RECT 42.510 0.155 44.890 4.280 ;
        RECT 45.730 0.155 48.110 4.280 ;
        RECT 48.950 0.155 51.330 4.280 ;
        RECT 52.170 0.155 54.550 4.280 ;
        RECT 55.390 0.155 60.990 4.280 ;
        RECT 61.830 0.155 64.210 4.280 ;
        RECT 65.050 0.155 67.430 4.280 ;
        RECT 68.270 0.155 70.650 4.280 ;
        RECT 71.490 0.155 73.870 4.280 ;
        RECT 74.710 0.155 77.090 4.280 ;
        RECT 77.930 0.155 83.530 4.280 ;
        RECT 84.370 0.155 86.750 4.280 ;
        RECT 87.590 0.155 89.970 4.280 ;
        RECT 90.810 0.155 93.190 4.280 ;
        RECT 94.030 0.155 96.410 4.280 ;
        RECT 97.250 0.155 102.850 4.280 ;
        RECT 103.690 0.155 106.070 4.280 ;
        RECT 106.910 0.155 109.290 4.280 ;
        RECT 110.130 0.155 112.510 4.280 ;
        RECT 113.350 0.155 115.730 4.280 ;
        RECT 116.570 0.155 122.170 4.280 ;
        RECT 123.010 0.155 125.390 4.280 ;
        RECT 126.230 0.155 128.610 4.280 ;
        RECT 129.450 0.155 131.830 4.280 ;
        RECT 132.670 0.155 135.050 4.280 ;
        RECT 135.890 0.155 138.270 4.280 ;
        RECT 139.110 0.155 144.710 4.280 ;
        RECT 145.550 0.155 147.930 4.280 ;
        RECT 148.770 0.155 151.150 4.280 ;
        RECT 151.990 0.155 154.370 4.280 ;
        RECT 155.210 0.155 157.590 4.280 ;
        RECT 158.430 0.155 164.030 4.280 ;
        RECT 164.870 0.155 167.250 4.280 ;
        RECT 168.090 0.155 170.470 4.280 ;
        RECT 171.310 0.155 173.690 4.280 ;
        RECT 174.530 0.155 176.910 4.280 ;
        RECT 177.750 0.155 183.350 4.280 ;
        RECT 184.190 0.155 186.570 4.280 ;
        RECT 187.410 0.155 189.790 4.280 ;
        RECT 190.630 0.155 193.010 4.280 ;
        RECT 193.850 0.155 196.230 4.280 ;
        RECT 197.070 0.155 199.450 4.280 ;
        RECT 200.290 0.155 205.890 4.280 ;
        RECT 206.730 0.155 209.110 4.280 ;
        RECT 209.950 0.155 212.330 4.280 ;
        RECT 213.170 0.155 215.550 4.280 ;
        RECT 216.390 0.155 218.770 4.280 ;
        RECT 219.610 0.155 225.210 4.280 ;
        RECT 226.050 0.155 228.430 4.280 ;
        RECT 229.270 0.155 231.650 4.280 ;
        RECT 232.490 0.155 234.870 4.280 ;
        RECT 235.710 0.155 238.090 4.280 ;
        RECT 238.930 0.155 244.530 4.280 ;
        RECT 245.370 0.155 247.750 4.280 ;
        RECT 248.590 0.155 250.970 4.280 ;
        RECT 251.810 0.155 254.190 4.280 ;
        RECT 255.030 0.155 257.410 4.280 ;
        RECT 258.250 0.155 260.630 4.280 ;
        RECT 261.470 0.155 267.070 4.280 ;
        RECT 267.910 0.155 270.290 4.280 ;
        RECT 271.130 0.155 273.510 4.280 ;
        RECT 274.350 0.155 276.730 4.280 ;
        RECT 277.570 0.155 279.950 4.280 ;
        RECT 280.790 0.155 286.390 4.280 ;
        RECT 287.230 0.155 289.610 4.280 ;
        RECT 290.450 0.155 292.830 4.280 ;
        RECT 293.670 0.155 296.050 4.280 ;
        RECT 296.890 0.155 299.270 4.280 ;
        RECT 300.110 0.155 305.710 4.280 ;
        RECT 306.550 0.155 308.930 4.280 ;
        RECT 309.770 0.155 312.150 4.280 ;
        RECT 312.990 0.155 315.370 4.280 ;
        RECT 316.210 0.155 318.590 4.280 ;
        RECT 319.430 0.155 325.030 4.280 ;
        RECT 325.870 0.155 328.250 4.280 ;
        RECT 329.090 0.155 331.470 4.280 ;
        RECT 332.310 0.155 334.690 4.280 ;
        RECT 335.530 0.155 337.910 4.280 ;
        RECT 338.750 0.155 341.130 4.280 ;
        RECT 341.970 0.155 347.570 4.280 ;
        RECT 348.410 0.155 350.790 4.280 ;
        RECT 351.630 0.155 354.010 4.280 ;
        RECT 354.850 0.155 357.230 4.280 ;
        RECT 358.070 0.155 360.450 4.280 ;
        RECT 361.290 0.155 366.890 4.280 ;
        RECT 367.730 0.155 370.110 4.280 ;
        RECT 370.950 0.155 373.330 4.280 ;
        RECT 374.170 0.155 376.550 4.280 ;
        RECT 377.390 0.155 379.770 4.280 ;
        RECT 380.610 0.155 386.210 4.280 ;
        RECT 387.050 0.155 389.430 4.280 ;
        RECT 390.270 0.155 392.650 4.280 ;
        RECT 393.490 0.155 395.050 4.280 ;
      LAYER met3 ;
        RECT 4.400 400.840 391.010 401.705 ;
        RECT 0.065 398.840 395.075 400.840 ;
        RECT 4.400 397.440 391.010 398.840 ;
        RECT 0.065 395.440 395.075 397.440 ;
        RECT 4.400 394.040 395.075 395.440 ;
        RECT 0.065 392.040 395.075 394.040 ;
        RECT 4.400 390.640 391.010 392.040 ;
        RECT 0.065 388.640 395.075 390.640 ;
        RECT 4.400 387.240 391.010 388.640 ;
        RECT 0.065 385.240 395.075 387.240 ;
        RECT 0.065 383.840 391.010 385.240 ;
        RECT 0.065 381.840 395.075 383.840 ;
        RECT 4.400 380.440 391.010 381.840 ;
        RECT 0.065 378.440 395.075 380.440 ;
        RECT 4.400 377.040 391.010 378.440 ;
        RECT 0.065 375.040 395.075 377.040 ;
        RECT 4.400 373.640 395.075 375.040 ;
        RECT 0.065 371.640 395.075 373.640 ;
        RECT 4.400 370.240 391.010 371.640 ;
        RECT 0.065 368.240 395.075 370.240 ;
        RECT 4.400 366.840 391.010 368.240 ;
        RECT 0.065 364.840 395.075 366.840 ;
        RECT 0.065 363.440 391.010 364.840 ;
        RECT 0.065 361.440 395.075 363.440 ;
        RECT 4.400 360.040 391.010 361.440 ;
        RECT 0.065 358.040 395.075 360.040 ;
        RECT 4.400 356.640 391.010 358.040 ;
        RECT 0.065 354.640 395.075 356.640 ;
        RECT 4.400 353.240 395.075 354.640 ;
        RECT 0.065 351.240 395.075 353.240 ;
        RECT 4.400 349.840 391.010 351.240 ;
        RECT 0.065 347.840 395.075 349.840 ;
        RECT 4.400 346.440 391.010 347.840 ;
        RECT 0.065 344.440 395.075 346.440 ;
        RECT 4.400 343.040 391.010 344.440 ;
        RECT 0.065 341.040 395.075 343.040 ;
        RECT 0.065 339.640 391.010 341.040 ;
        RECT 0.065 337.640 395.075 339.640 ;
        RECT 4.400 336.240 391.010 337.640 ;
        RECT 0.065 334.240 395.075 336.240 ;
        RECT 4.400 332.840 391.010 334.240 ;
        RECT 0.065 330.840 395.075 332.840 ;
        RECT 4.400 329.440 395.075 330.840 ;
        RECT 0.065 327.440 395.075 329.440 ;
        RECT 4.400 326.040 391.010 327.440 ;
        RECT 0.065 324.040 395.075 326.040 ;
        RECT 4.400 322.640 391.010 324.040 ;
        RECT 0.065 320.640 395.075 322.640 ;
        RECT 0.065 319.240 391.010 320.640 ;
        RECT 0.065 317.240 395.075 319.240 ;
        RECT 4.400 315.840 391.010 317.240 ;
        RECT 0.065 313.840 395.075 315.840 ;
        RECT 4.400 312.440 391.010 313.840 ;
        RECT 0.065 310.440 395.075 312.440 ;
        RECT 4.400 309.040 395.075 310.440 ;
        RECT 0.065 307.040 395.075 309.040 ;
        RECT 4.400 305.640 391.010 307.040 ;
        RECT 0.065 303.640 395.075 305.640 ;
        RECT 4.400 302.240 391.010 303.640 ;
        RECT 0.065 300.240 395.075 302.240 ;
        RECT 0.065 298.840 391.010 300.240 ;
        RECT 0.065 296.840 395.075 298.840 ;
        RECT 4.400 295.440 391.010 296.840 ;
        RECT 0.065 293.440 395.075 295.440 ;
        RECT 4.400 292.040 391.010 293.440 ;
        RECT 0.065 290.040 395.075 292.040 ;
        RECT 4.400 288.640 395.075 290.040 ;
        RECT 0.065 286.640 395.075 288.640 ;
        RECT 4.400 285.240 391.010 286.640 ;
        RECT 0.065 283.240 395.075 285.240 ;
        RECT 4.400 281.840 391.010 283.240 ;
        RECT 0.065 279.840 395.075 281.840 ;
        RECT 0.065 278.440 391.010 279.840 ;
        RECT 0.065 276.440 395.075 278.440 ;
        RECT 4.400 275.040 391.010 276.440 ;
        RECT 0.065 273.040 395.075 275.040 ;
        RECT 4.400 271.640 391.010 273.040 ;
        RECT 0.065 269.640 395.075 271.640 ;
        RECT 4.400 268.240 391.010 269.640 ;
        RECT 0.065 266.240 395.075 268.240 ;
        RECT 4.400 264.840 395.075 266.240 ;
        RECT 0.065 262.840 395.075 264.840 ;
        RECT 4.400 261.440 391.010 262.840 ;
        RECT 0.065 259.440 395.075 261.440 ;
        RECT 4.400 258.040 391.010 259.440 ;
        RECT 0.065 256.040 395.075 258.040 ;
        RECT 0.065 254.640 391.010 256.040 ;
        RECT 0.065 252.640 395.075 254.640 ;
        RECT 4.400 251.240 391.010 252.640 ;
        RECT 0.065 249.240 395.075 251.240 ;
        RECT 4.400 247.840 391.010 249.240 ;
        RECT 0.065 245.840 395.075 247.840 ;
        RECT 4.400 244.440 395.075 245.840 ;
        RECT 0.065 242.440 395.075 244.440 ;
        RECT 4.400 241.040 391.010 242.440 ;
        RECT 0.065 239.040 395.075 241.040 ;
        RECT 4.400 237.640 391.010 239.040 ;
        RECT 0.065 235.640 395.075 237.640 ;
        RECT 0.065 234.240 391.010 235.640 ;
        RECT 0.065 232.240 395.075 234.240 ;
        RECT 4.400 230.840 391.010 232.240 ;
        RECT 0.065 228.840 395.075 230.840 ;
        RECT 4.400 227.440 391.010 228.840 ;
        RECT 0.065 225.440 395.075 227.440 ;
        RECT 4.400 224.040 395.075 225.440 ;
        RECT 0.065 222.040 395.075 224.040 ;
        RECT 4.400 220.640 391.010 222.040 ;
        RECT 0.065 218.640 395.075 220.640 ;
        RECT 4.400 217.240 391.010 218.640 ;
        RECT 0.065 215.240 395.075 217.240 ;
        RECT 0.065 213.840 391.010 215.240 ;
        RECT 0.065 211.840 395.075 213.840 ;
        RECT 4.400 210.440 391.010 211.840 ;
        RECT 0.065 208.440 395.075 210.440 ;
        RECT 4.400 207.040 391.010 208.440 ;
        RECT 0.065 205.040 395.075 207.040 ;
        RECT 4.400 203.640 395.075 205.040 ;
        RECT 0.065 201.640 395.075 203.640 ;
        RECT 4.400 200.240 391.010 201.640 ;
        RECT 0.065 198.240 395.075 200.240 ;
        RECT 4.400 196.840 391.010 198.240 ;
        RECT 0.065 194.840 395.075 196.840 ;
        RECT 4.400 193.440 391.010 194.840 ;
        RECT 0.065 191.440 395.075 193.440 ;
        RECT 0.065 190.040 391.010 191.440 ;
        RECT 0.065 188.040 395.075 190.040 ;
        RECT 4.400 186.640 391.010 188.040 ;
        RECT 0.065 184.640 395.075 186.640 ;
        RECT 4.400 183.240 391.010 184.640 ;
        RECT 0.065 181.240 395.075 183.240 ;
        RECT 4.400 179.840 395.075 181.240 ;
        RECT 0.065 177.840 395.075 179.840 ;
        RECT 4.400 176.440 391.010 177.840 ;
        RECT 0.065 174.440 395.075 176.440 ;
        RECT 4.400 173.040 391.010 174.440 ;
        RECT 0.065 171.040 395.075 173.040 ;
        RECT 0.065 169.640 391.010 171.040 ;
        RECT 0.065 167.640 395.075 169.640 ;
        RECT 4.400 166.240 391.010 167.640 ;
        RECT 0.065 164.240 395.075 166.240 ;
        RECT 4.400 162.840 391.010 164.240 ;
        RECT 0.065 160.840 395.075 162.840 ;
        RECT 4.400 159.440 395.075 160.840 ;
        RECT 0.065 157.440 395.075 159.440 ;
        RECT 4.400 156.040 391.010 157.440 ;
        RECT 0.065 154.040 395.075 156.040 ;
        RECT 4.400 152.640 391.010 154.040 ;
        RECT 0.065 150.640 395.075 152.640 ;
        RECT 0.065 149.240 391.010 150.640 ;
        RECT 0.065 147.240 395.075 149.240 ;
        RECT 4.400 145.840 391.010 147.240 ;
        RECT 0.065 143.840 395.075 145.840 ;
        RECT 4.400 142.440 391.010 143.840 ;
        RECT 0.065 140.440 395.075 142.440 ;
        RECT 4.400 139.040 395.075 140.440 ;
        RECT 0.065 137.040 395.075 139.040 ;
        RECT 4.400 135.640 391.010 137.040 ;
        RECT 0.065 133.640 395.075 135.640 ;
        RECT 4.400 132.240 391.010 133.640 ;
        RECT 0.065 130.240 395.075 132.240 ;
        RECT 4.400 128.840 391.010 130.240 ;
        RECT 0.065 126.840 395.075 128.840 ;
        RECT 0.065 125.440 391.010 126.840 ;
        RECT 0.065 123.440 395.075 125.440 ;
        RECT 4.400 122.040 391.010 123.440 ;
        RECT 0.065 120.040 395.075 122.040 ;
        RECT 4.400 118.640 391.010 120.040 ;
        RECT 0.065 116.640 395.075 118.640 ;
        RECT 4.400 115.240 395.075 116.640 ;
        RECT 0.065 113.240 395.075 115.240 ;
        RECT 4.400 111.840 391.010 113.240 ;
        RECT 0.065 109.840 395.075 111.840 ;
        RECT 4.400 108.440 391.010 109.840 ;
        RECT 0.065 106.440 395.075 108.440 ;
        RECT 0.065 105.040 391.010 106.440 ;
        RECT 0.065 103.040 395.075 105.040 ;
        RECT 4.400 101.640 391.010 103.040 ;
        RECT 0.065 99.640 395.075 101.640 ;
        RECT 4.400 98.240 391.010 99.640 ;
        RECT 0.065 96.240 395.075 98.240 ;
        RECT 4.400 94.840 395.075 96.240 ;
        RECT 0.065 92.840 395.075 94.840 ;
        RECT 4.400 91.440 391.010 92.840 ;
        RECT 0.065 89.440 395.075 91.440 ;
        RECT 4.400 88.040 391.010 89.440 ;
        RECT 0.065 86.040 395.075 88.040 ;
        RECT 0.065 84.640 391.010 86.040 ;
        RECT 0.065 82.640 395.075 84.640 ;
        RECT 4.400 81.240 391.010 82.640 ;
        RECT 0.065 79.240 395.075 81.240 ;
        RECT 4.400 77.840 391.010 79.240 ;
        RECT 0.065 75.840 395.075 77.840 ;
        RECT 4.400 74.440 395.075 75.840 ;
        RECT 0.065 72.440 395.075 74.440 ;
        RECT 4.400 71.040 391.010 72.440 ;
        RECT 0.065 69.040 395.075 71.040 ;
        RECT 4.400 67.640 391.010 69.040 ;
        RECT 0.065 65.640 395.075 67.640 ;
        RECT 4.400 64.240 391.010 65.640 ;
        RECT 0.065 62.240 395.075 64.240 ;
        RECT 0.065 60.840 391.010 62.240 ;
        RECT 0.065 58.840 395.075 60.840 ;
        RECT 4.400 57.440 391.010 58.840 ;
        RECT 0.065 55.440 395.075 57.440 ;
        RECT 4.400 54.040 391.010 55.440 ;
        RECT 0.065 52.040 395.075 54.040 ;
        RECT 4.400 50.640 395.075 52.040 ;
        RECT 0.065 48.640 395.075 50.640 ;
        RECT 4.400 47.240 391.010 48.640 ;
        RECT 0.065 45.240 395.075 47.240 ;
        RECT 4.400 43.840 391.010 45.240 ;
        RECT 0.065 41.840 395.075 43.840 ;
        RECT 0.065 40.440 391.010 41.840 ;
        RECT 0.065 38.440 395.075 40.440 ;
        RECT 4.400 37.040 391.010 38.440 ;
        RECT 0.065 35.040 395.075 37.040 ;
        RECT 4.400 33.640 391.010 35.040 ;
        RECT 0.065 31.640 395.075 33.640 ;
        RECT 4.400 30.240 395.075 31.640 ;
        RECT 0.065 28.240 395.075 30.240 ;
        RECT 4.400 26.840 391.010 28.240 ;
        RECT 0.065 24.840 395.075 26.840 ;
        RECT 4.400 23.440 391.010 24.840 ;
        RECT 0.065 21.440 395.075 23.440 ;
        RECT 0.065 20.040 391.010 21.440 ;
        RECT 0.065 18.040 395.075 20.040 ;
        RECT 4.400 16.640 391.010 18.040 ;
        RECT 0.065 14.640 395.075 16.640 ;
        RECT 4.400 13.240 391.010 14.640 ;
        RECT 0.065 11.240 395.075 13.240 ;
        RECT 4.400 9.840 395.075 11.240 ;
        RECT 0.065 7.840 395.075 9.840 ;
        RECT 4.400 6.440 391.010 7.840 ;
        RECT 0.065 4.440 395.075 6.440 ;
        RECT 4.400 3.040 391.010 4.440 ;
        RECT 0.065 1.040 395.075 3.040 ;
        RECT 0.065 0.175 391.010 1.040 ;
      LAYER met4 ;
        RECT 3.055 10.240 20.640 393.545 ;
        RECT 23.040 10.240 23.940 393.545 ;
        RECT 26.340 10.240 174.240 393.545 ;
        RECT 176.640 10.240 177.540 393.545 ;
        RECT 179.940 10.240 327.840 393.545 ;
        RECT 330.240 10.240 331.140 393.545 ;
        RECT 333.540 10.240 389.290 393.545 ;
        RECT 3.055 7.655 389.290 10.240 ;
      LAYER met5 ;
        RECT 7.940 186.410 389.500 274.500 ;
        RECT 7.940 58.700 389.500 178.310 ;
  END
END picorv32
END LIBRARY

